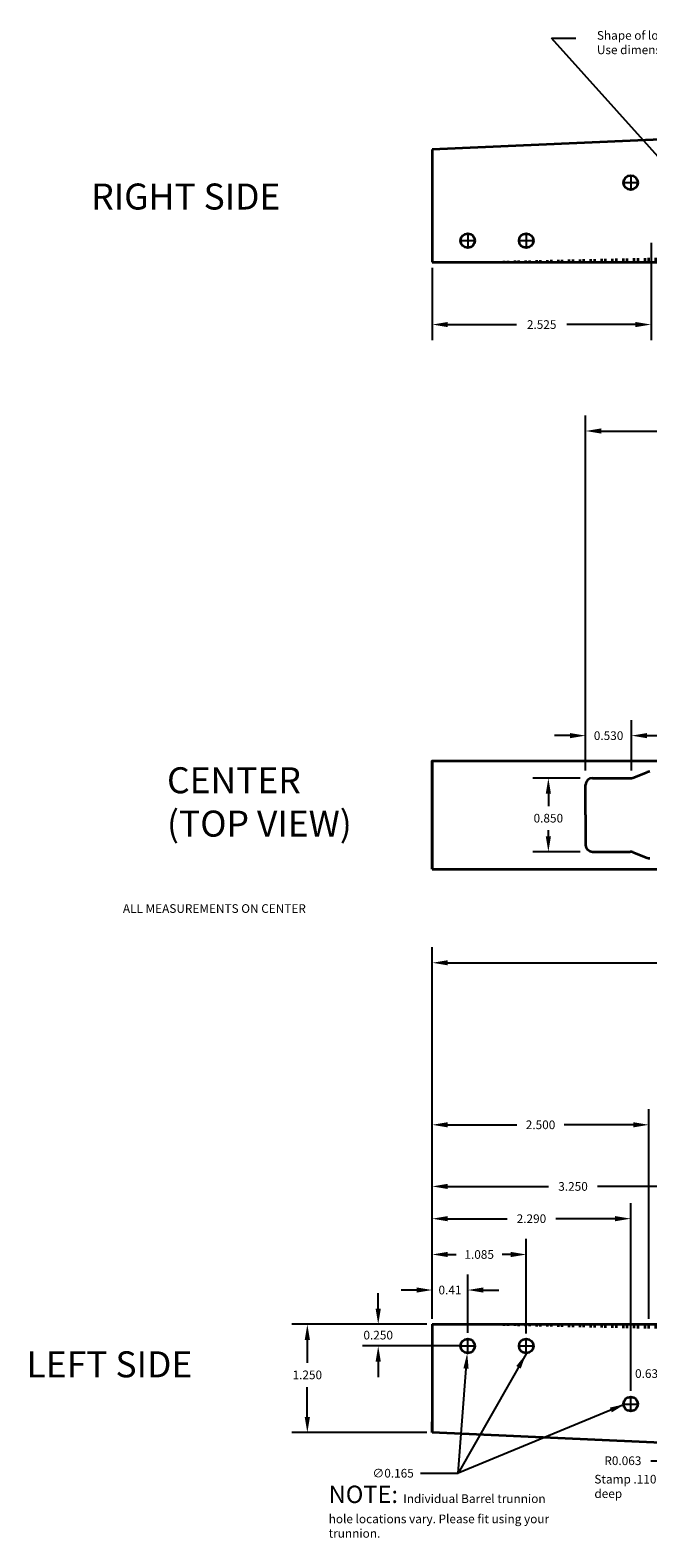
# Model space of a CAD drawing. Units: inches. Extents: x -3.6 to 16.1, y -0.6 to 17.2.
# Drawn here: x -3.6 to 3.5, y -0.2 to 17.2 of the extents above; entities that cross this region are included whole.
import ezdxf

# ---------------------------------------------------------------- set-up
doc = ezdxf.new("R2010")
doc.units = ezdxf.units.IN
doc.header["$MEASUREMENT"] = 0
doc.linetypes.add('ACAD_ISO03W100', pattern=[30, 12, -18])
doc.layers.add('dimensions', color=7, linetype='Continuous')
doc.layers.add('lines', color=1, linetype='Continuous', lineweight=35)
doc.dimstyles.get("Standard").update_dxf_attribs({"dimtxt": 0.18, "dimasz": 0.18, "dimexe": 0.18, "dimexo": 0.0625, "dimgap": 0.09, "dimtad": 0, "dimtih": 1, "dimtoh": 1, "dimdec": 3, "dimzin": 0, "dimdsep": 46, "dimtxsty": 'Standard', "dimcen": 0.09, "dimadec": 0, "dimazin": 0, "dimtfac": 1, "dimtdec": 3, "dimtofl": 0, "dimtmove": 0, "dimatfit": 3, "dimfxl": 0, "dimtolj": 1, "dimtzin": 0, "dimarcsym": 0})
pattern_1 = [(90, (0, 0), (-0.125, 3e-17), []), (90, (-0.0442, 0.0442), (-0.125, 3e-17), [])]

# ---------------------------------------------------------------- blocks, each defined once
blk = doc.blocks.new('*D7')
at = {"layer": 'Defpoints', "color": 0}
for p in [(2.77, 12.554), (2.77, 8.75), (11.25, 8.75)]:
    blk.add_point(p, dxfattribs=at)
at = {"layer": 'dimensions', "color": 0, "lineweight": -2}
for p, q in [((2.77, 8.812), (2.77, 12.734)), ((11.25, 8.812), (11.25, 12.734)), ((2.95, 12.554), (6.728, 12.554)), ((11.07, 12.554), (7.292, 12.554))]:
    blk.add_line(p, q, dxfattribs=at)
at = {"layer": 'dimensions', "color": 0}
for points in [[(2.95, 12.584), (2.95, 12.524), (2.77, 12.554)], [(11.07, 12.584), (11.07, 12.524), (11.25, 12.554)]]:
    blk.add_solid(points, dxfattribs=at)
at = {"layer": 'dimensions', "color": 0, "insert": (7.01, 12.554), "char_height": 0.1, "attachment_point": 5}
blk.add_mtext('\\A1;8.480', dxfattribs=at)
blk = doc.blocks.new('*D10')
at = {"layer": 'Defpoints', "color": 0}
for p in [(2.77, 8.55), (2.34, 7.7), (2.77, 7.7)]:
    blk.add_point(p, dxfattribs=at)
at = {"layer": 'dimensions', "color": 0, "lineweight": -2}
for p, q in [((2.708, 8.55), (2.16, 8.55)), ((2.34, 8.37), (2.34, 8.228)), ((2.34, 7.88), (2.34, 7.948)), ((2.708, 7.7), (2.16, 7.7))]:
    blk.add_line(p, q, dxfattribs=at)
at = {"layer": 'dimensions', "color": 0}
for points in [[(2.31, 8.37), (2.37, 8.37), (2.34, 8.55)], [(2.31, 7.88), (2.37, 7.88), (2.34, 7.7)]]:
    blk.add_solid(points, dxfattribs=at)
at = {"layer": 'dimensions', "color": 0, "insert": (2.34, 8.088), "char_height": 0.1, "attachment_point": 5}
blk.add_mtext('\\A1;0.850', dxfattribs=at)
blk = doc.blocks.new('*D11')
at = {"layer": 'Defpoints', "color": 0}
for p in [(1, 2.25), (-0.441, 1), (1, 1)]:
    blk.add_point(p, dxfattribs=at)
at = {"layer": 'dimensions', "color": 0, "lineweight": -2}
for p, q in [((0.938, 2.25), (-0.621, 2.25)), ((-0.441, 2.07), (-0.441, 1.806)), ((-0.441, 1.18), (-0.441, 1.526)), ((0.938, 1), (-0.621, 1))]:
    blk.add_line(p, q, dxfattribs=at)
at = {"layer": 'dimensions', "color": 0}
for points in [[(-0.471, 2.07), (-0.411, 2.07), (-0.441, 2.25)], [(-0.471, 1.18), (-0.411, 1.18), (-0.441, 1)]]:
    blk.add_solid(points, dxfattribs=at)
at = {"layer": 'dimensions', "color": 0, "insert": (-0.441, 1.666), "char_height": 0.1, "attachment_point": 5}
blk.add_mtext('\\A1;1.250', dxfattribs=at)
blk = doc.blocks.new('*D12')
at = {"layer": 'Defpoints', "color": 0}
for p in [(0.377, 2.25), (1, 2.25), (1.41, 2)]:
    blk.add_point(p, dxfattribs=at)
at = {"layer": 'dimensions', "color": 0, "lineweight": -2}
for p, q in [((0.377, 2.43), (0.377, 2.61)), ((0.938, 2.25), (0.197, 2.25)), ((1.347, 2), (0.197, 2)), ((0.377, 1.82), (0.377, 1.64))]:
    blk.add_line(p, q, dxfattribs=at)
at = {"layer": 'dimensions', "color": 0}
for points in [[(0.347, 2.43), (0.407, 2.43), (0.377, 2.25)], [(0.347, 1.82), (0.407, 1.82), (0.377, 2)]]:
    blk.add_solid(points, dxfattribs=at)
at = {"layer": 'dimensions', "color": 0, "insert": (0.377, 2.125), "char_height": 0.1, "attachment_point": 5}
blk.add_mtext('\\A1;0.250', dxfattribs=at)
blk = doc.blocks.new('*D13')
at = {"layer": 'Defpoints', "color": 0}
for p in [(1.404, 1.918), (1.416, 2.082)]:
    blk.add_point(p, dxfattribs=at)
at = {"layer": 'dimensions', "color": 0, "lineweight": -2}
for p, q in [((1.41, 1.91), (1.41, 2.09)), ((1.32, 2), (1.5, 2)), ((1.299, 0.532), (1.39, 1.738)), ((0.864, 0.532), (1.299, 0.532))]:
    blk.add_line(p, q, dxfattribs=at)
at = {"layer": 'dimensions', "color": 0}
blk.add_solid([(1.36, 1.741), (1.42, 1.736), (1.404, 1.918)], dxfattribs=at)
at = {"layer": 'dimensions', "color": 0, "insert": (0.549, 0.532), "char_height": 0.1, "attachment_point": 5}
blk.add_mtext('\\A1;∅0.165', dxfattribs=at)
blk = doc.blocks.new('*D14')
at = {"layer": 'Defpoints', "color": 0}
for p in [(3.29, 3.468), (1, 2.25), (3.29, 1.42)]:
    blk.add_point(p, dxfattribs=at)
at = {"layer": 'dimensions', "color": 0, "lineweight": -2}
for p, q in [((1, 2.312), (1, 3.648)), ((3.29, 1.482), (3.29, 3.648)), ((1.18, 3.468), (1.863, 3.468)), ((3.11, 3.468), (2.427, 3.468))]:
    blk.add_line(p, q, dxfattribs=at)
at = {"layer": 'dimensions', "color": 0}
for points in [[(1.18, 3.498), (1.18, 3.438), (1, 3.468)], [(3.11, 3.498), (3.11, 3.438), (3.29, 3.468)]]:
    blk.add_solid(points, dxfattribs=at)
at = {"layer": 'dimensions', "color": 0, "insert": (2.145, 3.468), "char_height": 0.1, "attachment_point": 5}
blk.add_mtext('\\A1;2.290', dxfattribs=at)
blk = doc.blocks.new('*D15')
at = {"layer": 'Defpoints', "color": 0}
for p in [(2.085, 3.055), (1, 2.25), (2.085, 2.083)]:
    blk.add_point(p, dxfattribs=at)
at = {"layer": 'dimensions', "color": 0, "lineweight": -2}
for p, q in [((1, 2.312), (1, 3.235)), ((2.085, 2.145), (2.085, 3.235)), ((1.18, 3.055), (1.277, 3.055)), ((1.905, 3.055), (1.808, 3.055))]:
    blk.add_line(p, q, dxfattribs=at)
at = {"layer": 'dimensions', "color": 0}
for points in [[(1.18, 3.085), (1.18, 3.025), (1, 3.055)], [(1.905, 3.085), (1.905, 3.025), (2.085, 3.055)]]:
    blk.add_solid(points, dxfattribs=at)
at = {"layer": 'dimensions', "color": 0, "insert": (1.542, 3.055), "char_height": 0.1, "attachment_point": 5}
blk.add_mtext('\\A1;1.085', dxfattribs=at)
blk = doc.blocks.new('*D16')
at = {"layer": 'Defpoints', "color": 0}
for p in [(1.41, 2.645), (1, 2.25), (1.41, 2.09)]:
    blk.add_point(p, dxfattribs=at)
at = {"layer": 'dimensions', "color": 0, "lineweight": -2}
for p, q in [((1, 2.313), (1, 2.825)), ((1.41, 2.153), (1.41, 2.825)), ((0.82, 2.645), (0.64, 2.645)), ((1.59, 2.645), (1.77, 2.645))]:
    blk.add_line(p, q, dxfattribs=at)
at = {"layer": 'dimensions', "color": 0}
for points in [[(0.82, 2.675), (0.82, 2.615), (1, 2.645)], [(1.59, 2.675), (1.59, 2.615), (1.41, 2.645)]]:
    blk.add_solid(points, dxfattribs=at)
at = {"layer": 'dimensions', "color": 0, "insert": (1.205, 2.645), "char_height": 0.1, "attachment_point": 5}
blk.add_mtext('\\A1;0.41', dxfattribs=at)
blk = doc.blocks.new('*D17')
at = {"layer": 'Defpoints', "color": 0}
for p in [(3.3, 9.04), (2.77, 8.575), (3.3, 8.575)]:
    blk.add_point(p, dxfattribs=at)
at = {"layer": 'dimensions', "color": 0, "lineweight": -2}
for p, q in [((2.77, 8.638), (2.77, 9.22)), ((3.3, 8.638), (3.3, 9.22)), ((2.59, 9.04), (2.41, 9.04)), ((3.48, 9.04), (3.66, 9.04))]:
    blk.add_line(p, q, dxfattribs=at)
at = {"layer": 'dimensions', "color": 0}
for points in [[(2.59, 9.07), (2.59, 9.01), (2.77, 9.04)], [(3.48, 9.07), (3.48, 9.01), (3.3, 9.04)]]:
    blk.add_solid(points, dxfattribs=at)
at = {"layer": 'dimensions', "color": 0, "insert": (3.035, 9.04), "char_height": 0.1, "attachment_point": 5}
blk.add_mtext('\\A1;0.530', dxfattribs=at)
blk = doc.blocks.new('*D48')
at = {"layer": 'Defpoints', "color": 0}
for p in [(1, 4.551), (1, 2.25), (3.5, 2.25)]:
    blk.add_point(p, dxfattribs=at)
at = {"layer": 'dimensions', "color": 0, "lineweight": -2}
for p, q in [((1, 2.312), (1, 4.731)), ((3.5, 2.312), (3.5, 4.731)), ((1.18, 4.551), (1.977, 4.551)), ((3.32, 4.551), (2.523, 4.551))]:
    blk.add_line(p, q, dxfattribs=at)
at = {"layer": 'dimensions', "color": 0}
for points in [[(1.18, 4.581), (1.18, 4.521), (1, 4.551)], [(3.32, 4.581), (3.32, 4.521), (3.5, 4.551)]]:
    blk.add_solid(points, dxfattribs=at)
at = {"layer": 'dimensions', "color": 0, "insert": (2.25, 4.551), "char_height": 0.1, "attachment_point": 5}
blk.add_mtext('\\A1;2.500', dxfattribs=at)
blk = doc.blocks.new('*D56')
at = {"layer": 'Defpoints', "color": 0}
for p in [(4.568, 1.681), (3.933, 1.332), (4.568, 1.332)]:
    blk.add_point(p, dxfattribs=at)
at = {"layer": 'dimensions', "color": 0, "lineweight": -2}
for p, q in [((3.933, 1.395), (3.933, 1.831)), ((4.568, 1.395), (4.568, 1.831)), ((3.933, 1.681), (3.752, 1.681)), ((4.388, 1.681), (4.112, 1.681))]:
    blk.add_line(p, q, dxfattribs=at)
at = {"layer": 'dimensions', "color": 0}
for points in [[(4.112, 1.711), (4.112, 1.651), (3.933, 1.681)], [(4.388, 1.711), (4.388, 1.651), (4.568, 1.681)]]:
    blk.add_solid(points, dxfattribs=at)
at = {"layer": 'dimensions', "color": 0, "insert": (3.511, 1.681), "char_height": 0.1, "attachment_point": 5}
blk.add_mtext('\\A1;0.635', dxfattribs=at)
blk = doc.blocks.new('*D57')
at = {"layer": 'Defpoints', "color": 0}
for p in [(1, 3.84), (1, 2.25), (4.25, 1.482)]:
    blk.add_point(p, dxfattribs=at)
at = {"layer": 'dimensions', "color": 0, "lineweight": -2}
for p, q in [((1, 2.312), (1, 4.02)), ((4.25, 1.545), (4.25, 4.02)), ((1.18, 3.84), (2.343, 3.84)), ((4.07, 3.84), (2.907, 3.84))]:
    blk.add_line(p, q, dxfattribs=at)
at = {"layer": 'dimensions', "color": 0}
for points in [[(1.18, 3.87), (1.18, 3.81), (1, 3.84)], [(4.07, 3.87), (4.07, 3.81), (4.25, 3.84)]]:
    blk.add_solid(points, dxfattribs=at)
at = {"layer": 'dimensions', "color": 0, "insert": (2.625, 3.84), "char_height": 0.1, "attachment_point": 5}
blk.add_mtext('\\A1;3.250', dxfattribs=at)
blk = doc.blocks.new('*D58')
at = {"layer": 'Defpoints', "color": 0}
for p in [(3.973, 1.274), (3.995, 1.332)]:
    blk.add_point(p, dxfattribs=at)
at = {"layer": 'dimensions', "color": 0, "lineweight": -2}
for p, q in [((3.995, 1.242), (3.995, 1.422)), ((3.905, 1.332), (4.085, 1.332)), ((3.753, 0.676), (3.911, 1.105)), ((3.523, 0.676), (3.753, 0.676))]:
    blk.add_line(p, q, dxfattribs=at)
at = {"layer": 'dimensions', "color": 0}
blk.add_solid([(3.883, 1.115), (3.939, 1.094), (3.973, 1.274)], dxfattribs=at)
at = {"layer": 'dimensions', "color": 0, "insert": (3.2, 0.676), "char_height": 0.1, "attachment_point": 5}
blk.add_mtext('\\A1;R0.063', dxfattribs=at)
blk = doc.blocks.new('*D70')
at = {"layer": 'Defpoints', "color": 0, "linetype": 'ACAD_ISO03W100'}
for p in [(11.25, 6.42), (1, 2.25), (11.25, 2.05)]:
    blk.add_point(p, dxfattribs=at)
at = {"layer": 'dimensions', "color": 0, "linetype": 'ACAD_ISO03W100', "lineweight": -2}
for p, q in [((1, 2.312), (1, 6.6)), ((11.25, 2.112), (11.25, 6.6)), ((1.18, 6.42), (5.818, 6.42)), ((11.07, 6.42), (6.432, 6.42))]:
    blk.add_line(p, q, dxfattribs=at)
at = {"layer": 'dimensions', "color": 0, "linetype": 'ACAD_ISO03W100'}
for points in [[(1.18, 6.45), (1.18, 6.39), (1, 6.42)], [(11.07, 6.45), (11.07, 6.39), (11.25, 6.42)]]:
    blk.add_solid(points, dxfattribs=at)
at = {"layer": 'dimensions', "color": 0, "linetype": 'ACAD_ISO03W100', "insert": (6.125, 6.42), "char_height": 0.1, "attachment_point": 5}
blk.add_mtext('\\A1;10.250', dxfattribs=at)
blk = doc.blocks.new('*D72')
at = {"layer": 'Defpoints', "color": 0, "linetype": 'ByBlock'}
for p in [(3.525, 14.785), (1, 14.5), (3.525, 13.782)]:
    blk.add_point(p, dxfattribs=at)
at = {"layer": 'dimensions', "color": 0, "linetype": 'ByBlock', "lineweight": -2}
for p, q in [((3.525, 14.723), (3.525, 13.602)), ((1, 14.438), (1, 13.602)), ((1.18, 13.782), (1.973, 13.782)), ((3.345, 13.782), (2.553, 13.782))]:
    blk.add_line(p, q, dxfattribs=at)
at = {"layer": 'dimensions', "color": 0, "linetype": 'ByBlock'}
for points in [[(1.18, 13.812), (1.18, 13.752), (1, 13.782)], [(3.345, 13.812), (3.345, 13.752), (3.525, 13.782)]]:
    blk.add_solid(points, dxfattribs=at)
at = {"layer": 'dimensions', "color": 0, "linetype": 'ByBlock', "insert": (2.263, 13.782), "char_height": 0.1, "attachment_point": 5}
blk.add_mtext('\\A1;2.525', dxfattribs=at)

msp = doc.modelspace()

# ---------------------------------------------------------------- hatches: boundary and pattern name
at = {"layer": 'lines'}
h = msp.add_hatch(dxfattribs=at)
h.set_pattern_fill('STEEL', color=256, angle=45, style=0)
h.set_pattern_definition(pattern_1)
edge = h.paths.add_edge_path()
edge.add_line((3.5, 14.55), (9.5, 14.55))
edge.add_line((10.95, 14.5), (1, 14.5))
h = msp.add_hatch(dxfattribs=at)
h.set_pattern_fill('STEEL', color=256, angle=45, style=0)
h.set_pattern_definition(pattern_1)
edge = h.paths.add_edge_path()
edge.add_line((3.5, 2.2), (9.5, 2.2))
edge.add_line((10.95, 2.25), (1, 2.25))

# ---------------------------------------------------------------- linework, layer by layer
at = {"layer": 'dimensions'}
for p, q in [((3.29, 15.51), (3.29, 15.33)), ((3.2, 15.42), (3.38, 15.42)), ((1.41, 14.84), (1.41, 14.66)), ((2.085, 14.84), (2.085, 14.66)), ((1.32, 14.75), (1.5, 14.75)), ((1.995, 14.75), (2.175, 14.75)), ((1.41, 1.91), (1.41, 2.09)), ((2.085, 1.91), (2.085, 2.09)), ((1.32, 2), (1.5, 2)), ((1.995, 2), (2.175, 2)), ((3.29, 1.24), (3.29, 1.42)), ((3.2, 1.33), (3.38, 1.33))]:
    msp.add_line(p, q, dxfattribs=at)
at = {"layer": 'lines', "color": 1}
for p, q in [((11.25, 16.25), (1, 15.8)), ((1, 15.8), (1, 14.5)), ((1, 8.75), (11.25, 8.75)), ((2.8481, 8.55), (3.2855, 8.55)), ((3.3135, 8.5552), (3.4815, 8.6198)), ((2.77, 8.125), (2.77, 8.4719)), ((2.77, 8.125), (2.77, 7.7781)), ((2.8481, 7.7), (3.2855, 7.7)), ((3.3135, 7.6948), (3.4815, 7.6302)), ((1, 7.5), (11.25, 7.5)), ((1, 2.25), (1, 1)), ((1, 1), (1, 1.125)), ((11.25, 0.55), (1, 1))]:
    msp.add_line(p, q, dxfattribs=at)
at = {"layer": 'lines', "linetype": 'ByBlock'}
for p, q in [((1, 14.5), (10.95, 14.5)), ((1, 2.25), (10.95, 2.25))]:
    msp.add_line(p, q, dxfattribs=at)
at = {"layer": 'lines', "color": 1}
msp.add_lwpolyline([(1, 7.5), (1, 7.5), (1, 8.75), (1, 8.75)], close=True, dxfattribs=at)
for centre in [(3.29, 15.42), (1.41, 14.75), (2.085, 14.75), (1.41, 2), (2.085, 2), (3.29, 1.33)]:
    msp.add_circle(centre, 0.0825, dxfattribs=at)
for centre, start, end in [((2.8481, 8.4719), 90, 180), ((3.2855, 8.6281), 270, 291.03751), ((3.5095, 8.5469), 90, 111.03751), ((2.8481, 7.7781), 180, 270), ((3.2855, 7.6219), 68.96249, 90), ((3.5095, 7.7031), 248.96249, 270)]:
    msp.add_arc(centre, 0.0781, start, end, dxfattribs=at)

# ---------------------------------------------------------------- texts
at = {"layer": 'dimensions'}
msp.add_text('LEFT SIDE', height=0.3, dxfattribs=at).set_placement((-3.6806, 1.638))
at = {"layer": 'dimensions', "linetype": 'ByBlock', "insert": (2.9004, 17.1677), "char_height": 0.1, "width": 2.3136, "attachment_point": 1}
msp.add_mtext('Shape of lower rail is not accurate. Use dimensions for location only.', dxfattribs=at)
at = {"layer": 'dimensions', "attachment_point": 1}
for s, insert, char_height, width in [('RIGHT SIDE', (-2.9345, 15.4087), 0.3, 3.5318), ('CENTER (TOP VIEW)', (-2.06, 8.6752), 0.3, 2.544428), ('ALL MEASUREMENTS ON CENTER', (-2.5689, 7.0956), 0.1, 2.836), ('NOTE: {\\H0.5x;Individual Barrel trunnion hole locations vary. Please fit using your  trunnion.}', (-0.1944, 0.3883), 0.2, 2.666396), ('Stamp .110 deep', (2.8714, 0.5132), 0.1, 0.998118)]:
    msp.add_mtext(s, dxfattribs=dict(at, insert=insert, char_height=char_height, width=width))

# ---------------------------------------------------------------- dimensions: what is measured, and where the dimension line sits
at = {"layer": 'dimensions', "linetype": 'ByBlock'}
dim = msp.add_linear_dim(base=(3.525, 13.7824), p1=(1, 14.5), p2=(3.525, 14.785), dimstyle='Standard', override={"dimtxt": 0.1}, dxfattribs=at)
dim.commit()
dim.dimension.update_dxf_attribs({"geometry": '*D72', "text_midpoint": (2.2625, 13.7824)})
at = {"layer": 'dimensions'}
for base, p1, p2, override, picture, middle in [((2.77, 12.5543), (11.25, 8.75), (2.77, 8.75), {"dimtxt": 0.1}, '*D7', (7.01, 12.5543)), ((3.3, 9.0399), (2.77, 8.575), (3.3, 8.575), {"dimtxt": 0.1}, '*D17', (3.035, 9.0399)), ((1, 4.551), (3.5, 2.25), (1, 2.25), {"dimtxt": 0.1}, '*D48', (2.25, 4.551)), ((1, 3.84), (4.25, 1.4823), (1, 2.25), {"dimtxt": 0.1}, '*D57', (2.625, 3.84)), ((3.29, 3.4681), (1, 2.25), (3.29, 1.42), {"dimtxt": 0.1}, '*D14', (2.145, 3.4681)), ((2.085, 3.0553), (1, 2.25), (2.085, 2.0825), {"dimtxt": 0.1}, '*D15', (1.5425, 3.0553)), ((4.5675, 1.6814), (3.9325, 1.3323), (4.5675, 1.3323), {"dimtxt": 0.1, "dimexe": 0.15, "dimgap": 0.05}, '*D56', (3.5108, 1.6814))]:
    dim = msp.add_linear_dim(base=base, p1=p1, p2=p2, dimstyle='Standard', override=override, dxfattribs=at)
    dim.commit()
    dim.dimension.update_dxf_attribs({"geometry": picture, "text_midpoint": middle, "dimtype": 160})
for base, p1, p2, picture, middle in [((2.3401, 7.7), (2.77, 8.55), (2.77, 7.7), '*D10', (2.3401, 8.088)), ((0.3773, 2.25), (1.41, 2), (1, 2.25), '*D12', (0.3773, 2.125)), ((-0.4409, 1), (1, 2.25), (1, 1), '*D11', (-0.4409, 1.6657))]:
    dim = msp.add_linear_dim(base=base, p1=p1, p2=p2, angle=90, dimstyle='Standard', override={"dimtxt": 0.1}, dxfattribs=at)
    dim.commit()
    dim.dimension.update_dxf_attribs({"geometry": picture, "text_midpoint": middle, "dimtype": 160})
at = {"layer": 'dimensions', "linetype": 'ACAD_ISO03W100'}
dim = msp.add_linear_dim(base=(11.25, 6.4198), p1=(1, 2.25), p2=(11.25, 2.05), dimstyle='Standard', override={"dimtxt": 0.1}, dxfattribs=at)
dim.commit()
dim.dimension.update_dxf_attribs({"geometry": '*D70', "text_midpoint": (6.125, 6.4198)})
at = {"layer": 'dimensions'}
dim = msp.add_linear_dim(base=(1.41, 2.6448), p1=(1, 2.25), p2=(1.41, 2.09), text='0.41', dimstyle='Standard', override={"dimtxt": 0.1}, dxfattribs=at)
dim.commit()
dim.dimension.update_dxf_attribs({"geometry": '*D16', "text_midpoint": (1.205, 2.6448), "dimtype": 160})
dim = msp.add_diameter_dim_2p(p1=(1.4162, 2.0823), p2=(1.4038, 1.9177), dimstyle='Standard', override={"dimtxt": 0.1}, dxfattribs=at)
dim.commit()
dim.dimension.update_dxf_attribs({"geometry": '*D13', "text_midpoint": (0.5486, 0.5323), "dimtype": 163})
dim = msp.add_radius_dim(center=(3.995, 1.3323), mpoint=(3.9734, 1.2737), dimstyle='Standard', override={"dimtxt": 0.1}, dxfattribs=at)
dim.commit()
dim.dimension.update_dxf_attribs({"geometry": '*D58', "text_midpoint": (3.1995, 0.6759), "dimtype": 164})

# ---------------------------------------------------------------- leaders
at = {"layer": 'dimensions', "linetype": 'ByBlock'}
msp.add_leader([(4.0247, 15.25), (2.3772, 17.0863), (2.6562, 17.0863)], dimstyle='Standard', override={"dimgap": 0.09, "dimtad": 0}, dxfattribs=at)
at = {"layer": 'dimensions'}
for points in [[(2.085, 1.91), (1.2986, 0.5323)], [(3.2275, 1.33), (1.2986, 0.5323)]]:
    msp.add_leader(points, dimstyle='Standard', override={"dimgap": 0.09, "dimtad": 0}, dxfattribs=at)

doc.saveas('drawing.dxf')
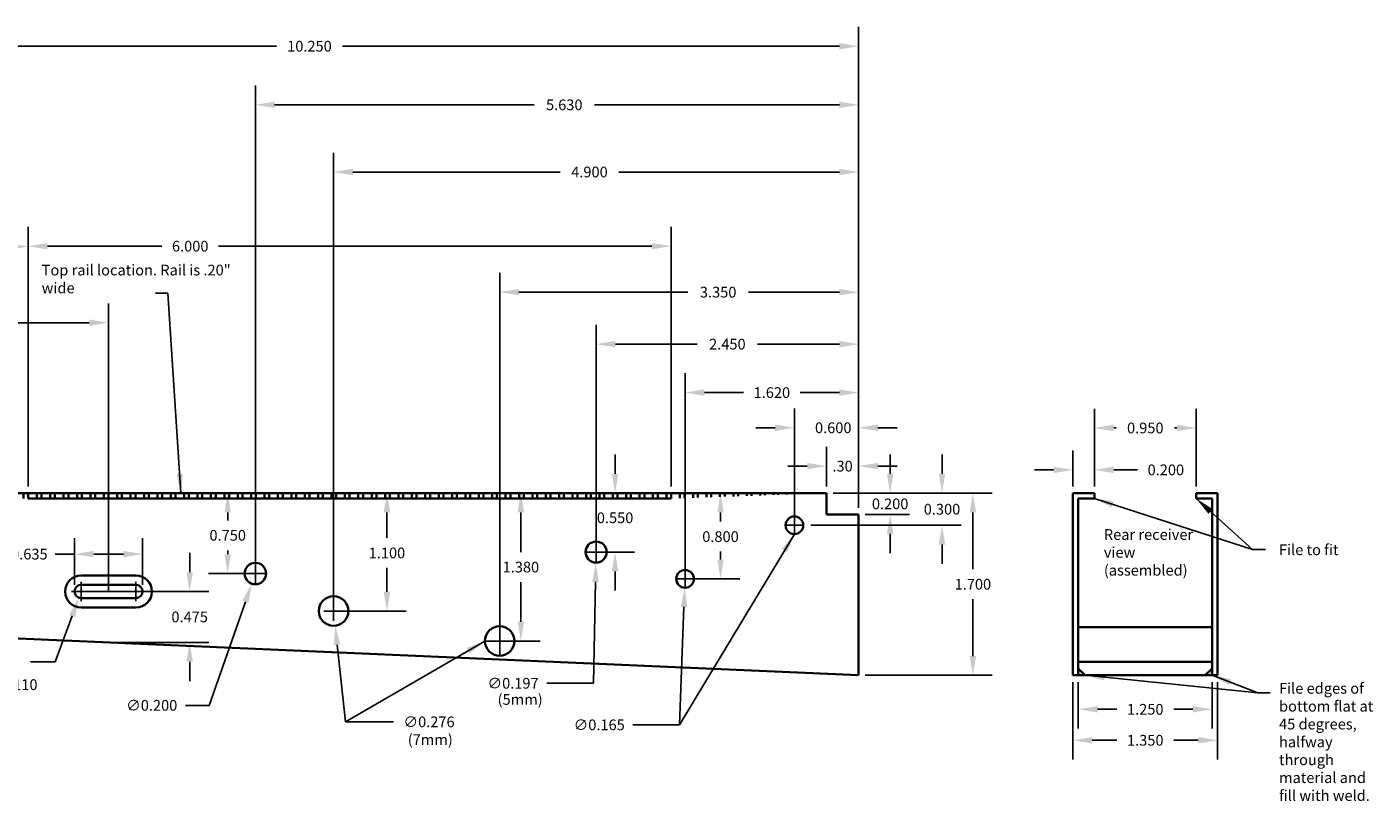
# Model space of a CAD drawing. Units: inches. Extents: x -3.6 to 16.1, y -0.6 to 17.2.
# Drawn here: x 3.5 to 16.1, y -0.6 to 6.6 of the extents above; entities that cross this region are included whole.
import ezdxf

# ---------------------------------------------------------------- set-up
doc = ezdxf.new("R2010")
doc.units = ezdxf.units.IN
doc.header["$MEASUREMENT"] = 0
doc.linetypes.add('ACAD_ISO03W100', pattern=[30, 12, -18])
doc.layers.add('dimensions', color=7, linetype='Continuous')
doc.layers.add('lines', color=1, linetype='Continuous', lineweight=35)
doc.dimstyles.get("Standard").update_dxf_attribs({"dimtxt": 0.18, "dimasz": 0.18, "dimexe": 0.18, "dimexo": 0.0625, "dimgap": 0.09, "dimtad": 0, "dimtih": 1, "dimtoh": 1, "dimdec": 3, "dimzin": 0, "dimdsep": 46, "dimtxsty": 'Standard', "dimcen": 0.09, "dimadec": 0, "dimazin": 0, "dimtfac": 1, "dimtdec": 3, "dimtofl": 0, "dimtmove": 0, "dimatfit": 3, "dimfxl": 0, "dimtolj": 1, "dimtzin": 0, "dimarcsym": 0})

# ---------------------------------------------------------------- blocks, each defined once
blk = doc.blocks.new('*D23')
at = {"layer": 'Defpoints', "color": 0}
for p in [(11.25, 5.873), (11.25, 2.25), (5.62, 1.5)]:
    blk.add_point(p, dxfattribs=at)
at = {"layer": 'dimensions', "color": 0, "lineweight": -2}
for p, q in [((5.62, 1.563), (5.62, 6.053)), ((11.25, 2.312), (11.25, 6.053)), ((5.8, 5.873), (8.221, 5.873)), ((11.07, 5.873), (8.785, 5.873))]:
    blk.add_line(p, q, dxfattribs=at)
at = {"layer": 'dimensions', "color": 0}
for points in [[(5.8, 5.903), (5.8, 5.843), (5.62, 5.873)], [(11.07, 5.903), (11.07, 5.843), (11.25, 5.873)]]:
    blk.add_solid(points, dxfattribs=at)
at = {"layer": 'dimensions', "color": 0, "insert": (8.503, 5.873), "char_height": 0.1, "attachment_point": 5}
blk.add_mtext('\\A1;5.630', dxfattribs=at)
blk = doc.blocks.new('*D24')
at = {"layer": 'Defpoints', "color": 0}
for p in [(6.35, 5.246), (11.25, 2.25), (6.35, 1.15)]:
    blk.add_point(p, dxfattribs=at)
at = {"layer": 'dimensions', "color": 0, "lineweight": -2}
for p, q in [((6.35, 1.213), (6.35, 5.426)), ((11.25, 2.312), (11.25, 5.426)), ((6.53, 5.246), (8.465, 5.246)), ((11.07, 5.246), (9.011, 5.246))]:
    blk.add_line(p, q, dxfattribs=at)
at = {"layer": 'dimensions', "color": 0}
for points in [[(6.53, 5.276), (6.53, 5.216), (6.35, 5.246)], [(11.07, 5.276), (11.07, 5.216), (11.25, 5.246)]]:
    blk.add_solid(points, dxfattribs=at)
at = {"layer": 'dimensions', "color": 0, "insert": (8.738, 5.246), "char_height": 0.1, "attachment_point": 5}
blk.add_mtext('\\A1;4.900', dxfattribs=at)
blk = doc.blocks.new('*D25')
at = {"layer": 'Defpoints', "color": 0}
for p in [(7.9, 4.125), (11.25, 2.25), (7.9, 0.87)]:
    blk.add_point(p, dxfattribs=at)
at = {"layer": 'dimensions', "color": 0, "lineweight": -2}
for p, q in [((7.9, 0.933), (7.9, 4.305)), ((11.25, 2.312), (11.25, 4.305)), ((8.08, 4.125), (9.657, 4.125)), ((11.07, 4.125), (10.221, 4.125))]:
    blk.add_line(p, q, dxfattribs=at)
at = {"layer": 'dimensions', "color": 0}
for points in [[(8.08, 4.155), (8.08, 4.095), (7.9, 4.125)], [(11.07, 4.155), (11.07, 4.095), (11.25, 4.125)]]:
    blk.add_solid(points, dxfattribs=at)
at = {"layer": 'dimensions', "color": 0, "insert": (9.939, 4.125), "char_height": 0.1, "attachment_point": 5}
blk.add_mtext('\\A1;3.350', dxfattribs=at)
blk = doc.blocks.new('*D26')
at = {"layer": 'Defpoints', "color": 0}
for p in [(8.8, 3.64), (11.25, 2.25), (8.8, 1.7)]:
    blk.add_point(p, dxfattribs=at)
at = {"layer": 'dimensions', "color": 0, "lineweight": -2}
for p, q in [((8.8, 1.762), (8.8, 3.82)), ((11.25, 2.312), (11.25, 3.82)), ((8.98, 3.64), (9.743, 3.64)), ((11.07, 3.64), (10.307, 3.64))]:
    blk.add_line(p, q, dxfattribs=at)
at = {"layer": 'dimensions', "color": 0}
for points in [[(8.98, 3.67), (8.98, 3.61), (8.8, 3.64)], [(11.07, 3.67), (11.07, 3.61), (11.25, 3.64)]]:
    blk.add_solid(points, dxfattribs=at)
at = {"layer": 'dimensions', "color": 0, "insert": (10.025, 3.64), "char_height": 0.1, "attachment_point": 5}
blk.add_mtext('\\A1;2.450', dxfattribs=at)
blk = doc.blocks.new('*D27')
at = {"layer": 'Defpoints', "color": 0}
for p in [(9.63, 3.188), (11.25, 2.25), (9.63, 1.45)]:
    blk.add_point(p, dxfattribs=at)
at = {"layer": 'dimensions', "color": 0, "lineweight": -2}
for p, q in [((9.63, 1.512), (9.63, 3.368)), ((11.25, 2.312), (11.25, 3.368)), ((9.81, 3.188), (10.175, 3.188)), ((11.07, 3.188), (10.705, 3.188))]:
    blk.add_line(p, q, dxfattribs=at)
at = {"layer": 'dimensions', "color": 0}
for points in [[(9.81, 3.218), (9.81, 3.158), (9.63, 3.188)], [(11.07, 3.218), (11.07, 3.158), (11.25, 3.188)]]:
    blk.add_solid(points, dxfattribs=at)
at = {"layer": 'dimensions', "color": 0, "insert": (10.44, 3.188), "char_height": 0.1, "attachment_point": 5}
blk.add_mtext('\\A1;1.620', dxfattribs=at)
blk = doc.blocks.new('*D28')
at = {"layer": 'Defpoints', "color": 0}
for p in [(9.63, 2.25), (9.961, 2.25), (9.63, 1.45)]:
    blk.add_point(p, dxfattribs=at)
at = {"layer": 'dimensions', "color": 0, "lineweight": -2}
for p, q in [((9.693, 2.25), (10.141, 2.25)), ((9.961, 2.07), (9.961, 1.984)), ((9.961, 1.63), (9.961, 1.704)), ((9.693, 1.45), (10.141, 1.45))]:
    blk.add_line(p, q, dxfattribs=at)
at = {"layer": 'dimensions', "color": 0}
for points in [[(9.931, 2.07), (9.991, 2.07), (9.961, 2.25)], [(9.931, 1.63), (9.991, 1.63), (9.961, 1.45)]]:
    blk.add_solid(points, dxfattribs=at)
at = {"layer": 'dimensions', "color": 0, "insert": (9.961, 1.844), "char_height": 0.1, "attachment_point": 5}
blk.add_mtext('\\A1;0.800', dxfattribs=at)
blk = doc.blocks.new('*D29')
at = {"layer": 'Defpoints', "color": 0}
for p in [(8.8, 2.25), (8.977, 2.25), (8.8, 1.7)]:
    blk.add_point(p, dxfattribs=at)
at = {"layer": 'dimensions', "color": 0, "lineweight": -2}
for p, q in [((8.977, 2.43), (8.977, 2.61)), ((8.863, 2.25), (9.157, 2.25)), ((8.863, 1.7), (9.157, 1.7)), ((8.977, 1.52), (8.977, 1.34))]:
    blk.add_line(p, q, dxfattribs=at)
at = {"layer": 'dimensions', "color": 0}
for points in [[(8.947, 2.43), (9.007, 2.43), (8.977, 2.25)], [(8.947, 1.52), (9.007, 1.52), (8.977, 1.7)]]:
    blk.add_solid(points, dxfattribs=at)
at = {"layer": 'dimensions', "color": 0, "insert": (8.977, 2.02), "char_height": 0.1, "attachment_point": 5}
blk.add_mtext('\\A1;0.550', dxfattribs=at)
blk = doc.blocks.new('*D30')
at = {"layer": 'Defpoints', "color": 0}
for p in [(5.362, 2.25), (5.62, 2.25), (5.62, 1.5)]:
    blk.add_point(p, dxfattribs=at)
at = {"layer": 'dimensions', "color": 0, "lineweight": -2}
for p, q in [((5.558, 2.25), (5.182, 2.25)), ((5.362, 2.07), (5.362, 1.996)), ((5.362, 1.68), (5.362, 1.716)), ((5.558, 1.5), (5.182, 1.5))]:
    blk.add_line(p, q, dxfattribs=at)
at = {"layer": 'dimensions', "color": 0}
for points in [[(5.332, 2.07), (5.392, 2.07), (5.362, 2.25)], [(5.332, 1.68), (5.392, 1.68), (5.362, 1.5)]]:
    blk.add_solid(points, dxfattribs=at)
at = {"layer": 'dimensions', "color": 0, "insert": (5.362, 1.856), "char_height": 0.1, "attachment_point": 5}
blk.add_mtext('\\A1;0.750', dxfattribs=at)
blk = doc.blocks.new('*D31')
at = {"layer": 'Defpoints', "color": 0}
for p in [(6.35, 2.25), (6.848, 2.25), (6.35, 1.15)]:
    blk.add_point(p, dxfattribs=at)
at = {"layer": 'dimensions', "color": 0, "lineweight": -2}
for p, q in [((6.413, 2.25), (7.028, 2.25)), ((6.848, 2.07), (6.848, 1.832)), ((6.848, 1.33), (6.848, 1.552)), ((6.413, 1.15), (7.028, 1.15))]:
    blk.add_line(p, q, dxfattribs=at)
at = {"layer": 'dimensions', "color": 0}
for points in [[(6.818, 2.07), (6.878, 2.07), (6.848, 2.25)], [(6.818, 1.33), (6.878, 1.33), (6.848, 1.15)]]:
    blk.add_solid(points, dxfattribs=at)
at = {"layer": 'dimensions', "color": 0, "insert": (6.848, 1.692), "char_height": 0.1, "attachment_point": 5}
blk.add_mtext('\\A1;1.100', dxfattribs=at)
blk = doc.blocks.new('*D32')
at = {"layer": 'Defpoints', "color": 0}
for p in [(7.9, 2.25), (8.098, 2.25), (7.9, 0.87)]:
    blk.add_point(p, dxfattribs=at)
at = {"layer": 'dimensions', "color": 0, "lineweight": -2}
for p, q in [((7.963, 2.25), (8.278, 2.25)), ((8.098, 2.07), (8.098, 1.7)), ((8.098, 1.05), (8.098, 1.42)), ((7.963, 0.87), (8.278, 0.87))]:
    blk.add_line(p, q, dxfattribs=at)
at = {"layer": 'dimensions', "color": 0}
for points in [[(8.068, 2.07), (8.128, 2.07), (8.098, 2.25)], [(8.068, 1.05), (8.128, 1.05), (8.098, 0.87)]]:
    blk.add_solid(points, dxfattribs=at)
at = {"layer": 'dimensions', "color": 0, "insert": (8.098, 1.56), "char_height": 0.1, "attachment_point": 5}
blk.add_mtext('\\A1;1.380', dxfattribs=at)
blk = doc.blocks.new('*D33')
at = {"layer": 'Defpoints', "color": 0}
for p in [(10.65, 2.86), (11.25, 2.25), (10.65, 1.95)]:
    blk.add_point(p, dxfattribs=at)
at = {"layer": 'dimensions', "color": 0, "lineweight": -2}
for p, q in [((10.65, 2.013), (10.65, 3.04)), ((11.25, 2.313), (11.25, 3.04)), ((10.47, 2.86), (10.29, 2.86)), ((11.43, 2.86), (11.61, 2.86))]:
    blk.add_line(p, q, dxfattribs=at)
at = {"layer": 'dimensions', "color": 0}
for points in [[(10.47, 2.89), (10.47, 2.83), (10.65, 2.86)], [(11.43, 2.89), (11.43, 2.83), (11.25, 2.86)]]:
    blk.add_solid(points, dxfattribs=at)
at = {"layer": 'dimensions', "color": 0, "insert": (11.013, 2.86), "char_height": 0.1, "attachment_point": 5}
blk.add_mtext('\\A1;0.600', dxfattribs=at)
blk = doc.blocks.new('*D34')
at = {"layer": 'Defpoints', "color": 0}
for p in [(11.25, 2.25), (11.25, 0.55), (12.316, 0.55)]:
    blk.add_point(p, dxfattribs=at)
at = {"layer": 'dimensions', "color": 0, "lineweight": -2}
for p, q in [((11.312, 2.25), (12.496, 2.25)), ((12.316, 2.07), (12.316, 1.54)), ((12.316, 0.73), (12.316, 1.26)), ((11.312, 0.55), (12.496, 0.55))]:
    blk.add_line(p, q, dxfattribs=at)
at = {"layer": 'dimensions', "color": 0}
for points in [[(12.286, 2.07), (12.346, 2.07), (12.316, 2.25)], [(12.286, 0.73), (12.346, 0.73), (12.316, 0.55)]]:
    blk.add_solid(points, dxfattribs=at)
at = {"layer": 'dimensions', "color": 0, "insert": (12.316, 1.4), "char_height": 0.1, "attachment_point": 5}
blk.add_mtext('\\A1;1.700', dxfattribs=at)
blk = doc.blocks.new('*D47')
at = {"layer": 'Defpoints', "color": 0}
for p in [(9.633, 1.532), (9.627, 1.368)]:
    blk.add_point(p, dxfattribs=at)
at = {"layer": 'dimensions', "color": 0, "lineweight": -2}
for p, q in [((9.63, 1.36), (9.63, 1.54)), ((9.54, 1.45), (9.72, 1.45)), ((9.579, 0.088), (9.62, 1.188)), ((9.144, 0.088), (9.579, 0.088))]:
    blk.add_line(p, q, dxfattribs=at)
at = {"layer": 'dimensions', "color": 0}
blk.add_solid([(9.59, 1.189), (9.65, 1.187), (9.627, 1.368)], dxfattribs=at)
at = {"layer": 'dimensions', "color": 0, "insert": (8.829, 0.088), "char_height": 0.1, "attachment_point": 5}
blk.add_mtext('\\A1;∅0.165', dxfattribs=at)
blk = doc.blocks.new('*D48')
at = {"layer": 'Defpoints', "color": 0}
for p in [(1, 4.551), (1, 2.25), (3.5, 2.25)]:
    blk.add_point(p, dxfattribs=at)
at = {"layer": 'dimensions', "color": 0, "lineweight": -2}
for p, q in [((1, 2.312), (1, 4.731)), ((3.5, 2.312), (3.5, 4.731)), ((1.18, 4.551), (1.977, 4.551)), ((3.32, 4.551), (2.523, 4.551))]:
    blk.add_line(p, q, dxfattribs=at)
at = {"layer": 'dimensions', "color": 0}
for points in [[(1.18, 4.581), (1.18, 4.521), (1, 4.551)], [(3.32, 4.581), (3.32, 4.521), (3.5, 4.551)]]:
    blk.add_solid(points, dxfattribs=at)
at = {"layer": 'dimensions', "color": 0, "insert": (2.25, 4.551), "char_height": 0.1, "attachment_point": 5}
blk.add_mtext('\\A1;2.500', dxfattribs=at)
blk = doc.blocks.new('*D49')
at = {"layer": 'Defpoints', "color": 0}
for p in [(3.5, 4.554), (3.5, 2.312), (9.5, 2.25)]:
    blk.add_point(p, dxfattribs=at)
at = {"layer": 'dimensions', "color": 0, "lineweight": -2}
for p, q in [((3.5, 2.375), (3.5, 4.734)), ((9.5, 2.312), (9.5, 4.734)), ((3.68, 4.554), (4.747, 4.554)), ((9.32, 4.554), (5.277, 4.554))]:
    blk.add_line(p, q, dxfattribs=at)
at = {"layer": 'dimensions', "color": 0}
for points in [[(3.68, 4.584), (3.68, 4.524), (3.5, 4.554)], [(9.32, 4.584), (9.32, 4.524), (9.5, 4.554)]]:
    blk.add_solid(points, dxfattribs=at)
at = {"layer": 'dimensions', "color": 0, "insert": (5.012, 4.554), "char_height": 0.1, "attachment_point": 5}
blk.add_mtext('\\A1;6.000', dxfattribs=at)
blk = doc.blocks.new('*D50')
at = {"layer": 'Defpoints', "color": 0}
for p in [(10.95, 2.25), (12.028, 2.25), (10.74, 1.95)]:
    blk.add_point(p, dxfattribs=at)
at = {"layer": 'dimensions', "color": 0, "lineweight": -2}
for p, q in [((12.028, 2.43), (12.028, 2.61)), ((11.012, 2.25), (12.208, 2.25)), ((10.803, 1.95), (12.208, 1.95)), ((12.028, 1.77), (12.028, 1.59))]:
    blk.add_line(p, q, dxfattribs=at)
at = {"layer": 'dimensions', "color": 0}
for points in [[(11.998, 2.43), (12.058, 2.43), (12.028, 2.25)], [(11.998, 1.77), (12.058, 1.77), (12.028, 1.95)]]:
    blk.add_solid(points, dxfattribs=at)
at = {"layer": 'dimensions', "color": 0, "insert": (12.028, 2.1), "char_height": 0.1, "attachment_point": 5}
blk.add_mtext('\\A1;0.300', dxfattribs=at)
blk = doc.blocks.new('*D51')
at = {"layer": 'Defpoints', "color": 0}
for p in [(10.95, 2.25), (11.25, 2.05), (11.544, 2.05)]:
    blk.add_point(p, dxfattribs=at)
at = {"layer": 'dimensions', "color": 0, "lineweight": -2}
for p, q in [((11.544, 2.43), (11.544, 2.61)), ((11.012, 2.25), (11.724, 2.25)), ((11.312, 2.05), (11.724, 2.05)), ((11.544, 1.87), (11.544, 1.69))]:
    blk.add_line(p, q, dxfattribs=at)
at = {"layer": 'dimensions', "color": 0}
for points in [[(11.514, 2.43), (11.574, 2.43), (11.544, 2.25)], [(11.514, 1.87), (11.574, 1.87), (11.544, 2.05)]]:
    blk.add_solid(points, dxfattribs=at)
at = {"layer": 'dimensions', "color": 0, "insert": (11.544, 2.15), "char_height": 0.1, "attachment_point": 5}
blk.add_mtext('\\A1;0.200', dxfattribs=at)
blk = doc.blocks.new('*D52')
at = {"layer": 'Defpoints', "color": 0}
for p in [(10.95, 2.502), (10.95, 2.25), (11.25, 2.05)]:
    blk.add_point(p, dxfattribs=at)
at = {"layer": 'dimensions', "color": 0, "lineweight": -2}
for p, q in [((10.95, 2.312), (10.95, 2.682)), ((11.25, 2.112), (11.25, 2.682)), ((10.77, 2.502), (10.59, 2.502)), ((11.43, 2.502), (11.61, 2.502))]:
    blk.add_line(p, q, dxfattribs=at)
at = {"layer": 'dimensions', "color": 0}
for points in [[(10.77, 2.532), (10.77, 2.472), (10.95, 2.502)], [(11.43, 2.532), (11.43, 2.472), (11.25, 2.502)]]:
    blk.add_solid(points, dxfattribs=at)
at = {"layer": 'dimensions', "color": 0, "insert": (11.1, 2.502), "char_height": 0.1, "attachment_point": 5}
blk.add_mtext('\\A1;.30', dxfattribs=at)
blk = doc.blocks.new('*D56')
at = {"layer": 'Defpoints', "color": 0}
for p in [(4.568, 1.681), (3.933, 1.332), (4.568, 1.332)]:
    blk.add_point(p, dxfattribs=at)
at = {"layer": 'dimensions', "color": 0, "lineweight": -2}
for p, q in [((3.933, 1.395), (3.933, 1.831)), ((4.568, 1.395), (4.568, 1.831)), ((3.933, 1.681), (3.752, 1.681)), ((4.388, 1.681), (4.112, 1.681))]:
    blk.add_line(p, q, dxfattribs=at)
at = {"layer": 'dimensions', "color": 0}
for points in [[(4.112, 1.711), (4.112, 1.651), (3.933, 1.681)], [(4.388, 1.711), (4.388, 1.651), (4.568, 1.681)]]:
    blk.add_solid(points, dxfattribs=at)
at = {"layer": 'dimensions', "color": 0, "insert": (3.511, 1.681), "char_height": 0.1, "attachment_point": 5}
blk.add_mtext('\\A1;0.635', dxfattribs=at)
blk = doc.blocks.new('*D57')
at = {"layer": 'Defpoints', "color": 0}
for p in [(1, 3.84), (1, 2.25), (4.25, 1.482)]:
    blk.add_point(p, dxfattribs=at)
at = {"layer": 'dimensions', "color": 0, "lineweight": -2}
for p, q in [((1, 2.312), (1, 4.02)), ((4.25, 1.545), (4.25, 4.02)), ((1.18, 3.84), (2.343, 3.84)), ((4.07, 3.84), (2.907, 3.84))]:
    blk.add_line(p, q, dxfattribs=at)
at = {"layer": 'dimensions', "color": 0}
for points in [[(1.18, 3.87), (1.18, 3.81), (1, 3.84)], [(4.07, 3.87), (4.07, 3.81), (4.25, 3.84)]]:
    blk.add_solid(points, dxfattribs=at)
at = {"layer": 'dimensions', "color": 0, "insert": (2.625, 3.84), "char_height": 0.1, "attachment_point": 5}
blk.add_mtext('\\A1;3.250', dxfattribs=at)
blk = doc.blocks.new('*D58')
at = {"layer": 'Defpoints', "color": 0}
for p in [(3.973, 1.274), (3.995, 1.332)]:
    blk.add_point(p, dxfattribs=at)
at = {"layer": 'dimensions', "color": 0, "lineweight": -2}
for p, q in [((3.995, 1.242), (3.995, 1.422)), ((3.905, 1.332), (4.085, 1.332)), ((3.753, 0.676), (3.911, 1.105)), ((3.523, 0.676), (3.753, 0.676))]:
    blk.add_line(p, q, dxfattribs=at)
at = {"layer": 'dimensions', "color": 0}
blk.add_solid([(3.883, 1.115), (3.939, 1.094), (3.973, 1.274)], dxfattribs=at)
at = {"layer": 'dimensions', "color": 0, "insert": (3.2, 0.676), "char_height": 0.1, "attachment_point": 5}
blk.add_mtext('\\A1;R0.063', dxfattribs=at)
blk = doc.blocks.new('*D59')
at = {"layer": 'Defpoints', "color": 0}
for p in [(4.25, 1.332), (4.25, 0.857), (5.007, 0.857)]:
    blk.add_point(p, dxfattribs=at)
at = {"layer": 'dimensions', "color": 0, "lineweight": -2}
for p, q in [((5.007, 1.512), (5.007, 1.692)), ((4.312, 1.332), (5.187, 1.332)), ((4.312, 0.857), (5.187, 0.857)), ((5.007, 0.677), (5.007, 0.497))]:
    blk.add_line(p, q, dxfattribs=at)
at = {"layer": 'dimensions', "color": 0}
for points in [[(4.977, 1.512), (5.037, 1.512), (5.007, 1.332)], [(4.977, 0.677), (5.037, 0.677), (5.007, 0.857)]]:
    blk.add_solid(points, dxfattribs=at)
at = {"layer": 'dimensions', "color": 0, "insert": (5.007, 1.095), "char_height": 0.1, "attachment_point": 5}
blk.add_mtext('\\A1;0.475', dxfattribs=at)
blk = doc.blocks.new('*D60')
at = {"layer": 'Defpoints', "color": 0}
for p in [(5.653, 1.594), (5.587, 1.406)]:
    blk.add_point(p, dxfattribs=at)
at = {"layer": 'dimensions', "color": 0, "lineweight": -2}
for p, q in [((5.62, 1.41), (5.62, 1.59)), ((5.53, 1.5), (5.71, 1.5)), ((5.19, 0.27), (5.528, 1.236)), ((4.968, 0.27), (5.19, 0.27))]:
    blk.add_line(p, q, dxfattribs=at)
at = {"layer": 'dimensions', "color": 0}
blk.add_solid([(5.499, 1.246), (5.556, 1.226), (5.587, 1.406)], dxfattribs=at)
at = {"layer": 'dimensions', "color": 0, "insert": (4.653, 0.27), "char_height": 0.1, "attachment_point": 5}
blk.add_mtext('\\A1;∅0.200', dxfattribs=at)
blk = doc.blocks.new('*D61')
at = {"layer": 'Defpoints', "color": 0}
for p in [(14.4, 2.858), (13.45, 2.25), (14.4, 2.25)]:
    blk.add_point(p, dxfattribs=at)
at = {"layer": 'dimensions', "color": 0, "lineweight": -2}
for p, q in [((13.45, 2.312), (13.45, 3.038)), ((14.4, 2.312), (14.4, 3.038)), ((13.63, 2.858), (13.652, 2.858)), ((14.22, 2.858), (14.198, 2.858))]:
    blk.add_line(p, q, dxfattribs=at)
at = {"layer": 'dimensions', "color": 0}
for points in [[(13.63, 2.888), (13.63, 2.828), (13.45, 2.858)], [(14.22, 2.888), (14.22, 2.828), (14.4, 2.858)]]:
    blk.add_solid(points, dxfattribs=at)
at = {"layer": 'dimensions', "color": 0, "insert": (13.925, 2.858), "char_height": 0.1, "attachment_point": 5}
blk.add_mtext('\\A1;0.950', dxfattribs=at)
blk = doc.blocks.new('*D62')
at = {"layer": 'Defpoints', "color": 0}
for p in [(13.25, 2.467), (13.25, 2.25), (13.45, 2.25)]:
    blk.add_point(p, dxfattribs=at)
at = {"layer": 'dimensions', "color": 0, "lineweight": -2}
for p, q in [((13.25, 2.312), (13.25, 2.647)), ((13.45, 2.312), (13.45, 2.647)), ((13.07, 2.467), (12.89, 2.467)), ((13.63, 2.467), (13.852, 2.467))]:
    blk.add_line(p, q, dxfattribs=at)
at = {"layer": 'dimensions', "color": 0}
for points in [[(13.07, 2.497), (13.07, 2.437), (13.25, 2.467)], [(13.63, 2.497), (13.63, 2.437), (13.45, 2.467)]]:
    blk.add_solid(points, dxfattribs=at)
at = {"layer": 'dimensions', "color": 0, "insert": (14.117, 2.467), "char_height": 0.1, "attachment_point": 5}
blk.add_mtext('\\A1;0.200', dxfattribs=at)
blk = doc.blocks.new('*D63')
at = {"layer": 'Defpoints', "color": 0}
for p in [(13.25, 0.55), (14.6, 0.55), (14.6, -0.056)]:
    blk.add_point(p, dxfattribs=at)
at = {"layer": 'dimensions', "color": 0, "lineweight": -2}
for p, q in [((13.25, 0.487), (13.25, -0.236)), ((14.6, 0.487), (14.6, -0.236)), ((13.43, -0.056), (13.66, -0.056)), ((14.42, -0.056), (14.19, -0.056))]:
    blk.add_line(p, q, dxfattribs=at)
at = {"layer": 'dimensions', "color": 0}
for points in [[(13.43, -0.026), (13.43, -0.086), (13.25, -0.056)], [(14.42, -0.026), (14.42, -0.086), (14.6, -0.056)]]:
    blk.add_solid(points, dxfattribs=at)
at = {"layer": 'dimensions', "color": 0, "insert": (13.925, -0.056), "char_height": 0.1, "attachment_point": 5}
blk.add_mtext('\\A1;1.350', dxfattribs=at)
blk = doc.blocks.new('*D64')
at = {"layer": 'Defpoints', "color": 0}
for p in [(13.3, 0.55), (14.55, 0.55), (14.55, 0.233)]:
    blk.add_point(p, dxfattribs=at)
at = {"layer": 'dimensions', "color": 0, "lineweight": -2}
for p, q in [((13.3, 0.487), (13.3, 0.053)), ((14.55, 0.487), (14.55, 0.053)), ((13.48, 0.233), (13.66, 0.233)), ((14.37, 0.233), (14.19, 0.233))]:
    blk.add_line(p, q, dxfattribs=at)
at = {"layer": 'dimensions', "color": 0}
for points in [[(13.48, 0.263), (13.48, 0.203), (13.3, 0.233)], [(14.37, 0.263), (14.37, 0.203), (14.55, 0.233)]]:
    blk.add_solid(points, dxfattribs=at)
at = {"layer": 'dimensions', "color": 0, "insert": (13.925, 0.233), "char_height": 0.1, "attachment_point": 5}
blk.add_mtext('\\A1;1.250', dxfattribs=at)
blk = doc.blocks.new('*D67')
at = {"layer": 'Defpoints', "color": 0}
for p in [(6.335, 1.287), (6.365, 1.013)]:
    blk.add_point(p, dxfattribs=at)
at = {"layer": 'dimensions', "color": 0, "lineweight": -2}
for p, q in [((6.26, 1.15), (6.44, 1.15)), ((6.35, 1.06), (6.35, 1.24)), ((6.461, 0.116), (6.384, 0.834)), ((6.909, 0.116), (6.461, 0.116))]:
    blk.add_line(p, q, dxfattribs=at)
at = {"layer": 'dimensions', "color": 0}
blk.add_solid([(6.414, 0.837), (6.354, 0.831), (6.365, 1.013)], dxfattribs=at)
at = {"layer": 'dimensions', "color": 0, "insert": (7.241, 0.116), "char_height": 0.1, "attachment_point": 5}
blk.add_mtext('\\A1;∅0.276', dxfattribs=at)
blk = doc.blocks.new('*D68')
at = {"layer": 'Defpoints', "color": 0}
for p in [(8.802, 1.798), (8.798, 1.602)]:
    blk.add_point(p, dxfattribs=at)
at = {"layer": 'dimensions', "color": 0, "lineweight": -2}
for p, q in [((8.8, 1.61), (8.8, 1.79)), ((8.71, 1.7), (8.89, 1.7)), ((8.775, 0.476), (8.794, 1.422)), ((8.34, 0.476), (8.775, 0.476))]:
    blk.add_line(p, q, dxfattribs=at)
at = {"layer": 'dimensions', "color": 0}
blk.add_solid([(8.764, 1.422), (8.824, 1.421), (8.798, 1.602)], dxfattribs=at)
at = {"layer": 'dimensions', "color": 0, "insert": (8.025, 0.476), "char_height": 0.1, "attachment_point": 5}
blk.add_mtext('\\A1;∅0.197', dxfattribs=at)
blk = doc.blocks.new('*D70')
at = {"layer": 'Defpoints', "color": 0, "linetype": 'ACAD_ISO03W100'}
for p in [(11.25, 6.42), (1, 2.25), (11.25, 2.05)]:
    blk.add_point(p, dxfattribs=at)
at = {"layer": 'dimensions', "color": 0, "linetype": 'ACAD_ISO03W100', "lineweight": -2}
for p, q in [((1, 2.312), (1, 6.6)), ((11.25, 2.112), (11.25, 6.6)), ((1.18, 6.42), (5.818, 6.42)), ((11.07, 6.42), (6.432, 6.42))]:
    blk.add_line(p, q, dxfattribs=at)
at = {"layer": 'dimensions', "color": 0, "linetype": 'ACAD_ISO03W100'}
for points in [[(1.18, 6.45), (1.18, 6.39), (1, 6.42)], [(11.07, 6.45), (11.07, 6.39), (11.25, 6.42)]]:
    blk.add_solid(points, dxfattribs=at)
at = {"layer": 'dimensions', "color": 0, "linetype": 'ACAD_ISO03W100', "insert": (6.125, 6.42), "char_height": 0.1, "attachment_point": 5}
blk.add_mtext('\\A1;10.250', dxfattribs=at)

msp = doc.modelspace()

# ---------------------------------------------------------------- hatches: boundary and pattern name
at = {"layer": 'lines'}
h = msp.add_hatch(dxfattribs=at)
h.set_pattern_fill('STEEL', color=256, angle=45, style=0)
h.set_pattern_definition([(90, (0, 0), (-0.125, 3e-17), []), (90, (-0.0442, 0.0442), (-0.125, 3e-17), [])])
edge = h.paths.add_edge_path()
edge.add_line((3.5, 2.2), (9.5, 2.2))
edge.add_line((10.95, 2.25), (1, 2.25))
h = msp.add_hatch(color=1, dxfattribs=at)
h.paths.add_polyline_path([(14.55, 0.55), (14.55, 0.615), (14.485, 0.55)])
h.paths.add_polyline_path([(13.365, 0.55), (13.3, 0.615), (13.3, 0.55)])

# ---------------------------------------------------------------- linework, layer by layer
at = {"layer": 'dimensions'}
for p, q in [((10.65, 1.86), (10.65, 2.04)), ((10.56, 1.95), (10.74, 1.95)), ((8.8, 1.61), (8.8, 1.79)), ((8.71, 1.7), (8.89, 1.7)), ((4.25, 1.5448), (4.25, 1.3323)), ((5.62, 1.41), (5.62, 1.59)), ((9.63, 1.36), (9.63, 1.54)), ((3.995, 1.2423), (3.995, 1.4223)), ((4.505, 1.2423), (4.505, 1.4223)), ((5.53, 1.5), (5.71, 1.5)), ((9.54, 1.45), (9.72, 1.45)), ((3.905, 1.3323), (4.085, 1.3323)), ((4.085, 1.3323), (4.415, 1.3323)), ((4.415, 1.3323), (4.595, 1.3323)), ((6.26, 1.15), (6.44, 1.15)), ((6.35, 1.06), (6.35, 1.24)), ((7.9, 0.7315), (7.9, 0.96)), ((7.762, 0.87), (7.99, 0.87))]:
    msp.add_line(p, q, dxfattribs=at)
at = {"layer": 'lines', "linetype": 'ByBlock'}
msp.add_line((1, 2.25), (10.95, 2.25), dxfattribs=at)
at = {"layer": 'lines', "color": 1}
for p, q in [((3.5, 2.25), (3.5, 2.2)), ((3.5, 2.2), (9.5, 2.2)), ((9.5, 2.25), (9.5, 2.2)), ((10.95, 2.25), (10.95, 2.05)), ((13.25, 0.55), (13.25, 2.25)), ((13.25, 2.25), (13.45, 2.25)), ((13.3, 2.2), (13.45, 2.2)), ((13.3, 0.55), (13.3, 2.2)), ((13.45, 2.25), (13.45, 2.2)), ((14.6, 2.25), (14.4, 2.25)), ((14.4, 2.25), (14.4, 2.2)), ((14.4, 2.2), (14.55, 2.2)), ((14.55, 0.55), (14.55, 2.2)), ((14.6, 0.55), (14.6, 2.25)), ((11.25, 2.05), (10.95, 2.05)), ((11.25, 2.05), (11.25, 0.55)), ((3.995, 1.4823), (4.505, 1.4823)), ((3.995, 1.3948), (4.505, 1.3948)), ((3.995, 1.2698), (4.505, 1.2698)), ((3.995, 1.1823), (4.505, 1.1823)), ((11.25, 0.55), (1, 1)), ((13.3, 1), (14.55, 1)), ((11.25, 0.55), (11.25, 0.675)), ((14.55, 0.675), (13.3, 0.675)), ((13.25, 0.55), (13.3, 0.55)), ((13.3, 0.615), (13.365, 0.55)), ((13.3, 0.55), (14.55, 0.55)), ((14.485, 0.55), (14.55, 0.615)), ((14.6, 0.55), (14.55, 0.55))]:
    msp.add_line(p, q, dxfattribs=at)
for centre, radius in [((10.65, 1.95), 0.0825), ((8.8, 1.7), 0.0985), ((5.62, 1.5), 0.1), ((9.63, 1.45), 0.0825), ((6.35, 1.15), 0.138), ((7.9, 0.87), 0.138)]:
    msp.add_circle(centre, radius, dxfattribs=at)
for centre, radius, start, end in [((3.995, 1.3323), 0.15, 90, 270), ((3.995, 1.3323), 0.0625, 90, 180), ((4.505, 1.3323), 0.15, 270, 90), ((4.505, 1.3323), 0.0625, 0, 90), ((3.995, 1.3323), 0.0625, 180, 270), ((4.505, 1.3323), 0.0625, 270, 0)]:
    msp.add_arc(centre, radius, start, end, dxfattribs=at)

# ---------------------------------------------------------------- texts
at = {"layer": 'dimensions'}
msp.add_text('(7mm)', height=0.1, dxfattribs=at).set_placement((7.0422, -0.1001))
at = {"layer": 'dimensions', "char_height": 0.1, "attachment_point": 1}
for s, insert, width in [('Top rail location. Rail is .20" wide', (3.626, 4.3812), 1.9884), ('Rear receiver view (assembled)', (13.5384, 1.9138), 0.8743), ('File to fit', (15.1726, 1.7717), 1.006781), ('Stamp .110 deep', (2.8714, 0.5132), 0.998118), ('(5mm)', (7.8809, 0.3749), 0.4842), ('File edges of bottom flat at 45 degrees, halfway through material and fill with weld.', (15.1732, 0.4785), 0.9047)]:
    msp.add_mtext(s, dxfattribs=dict(at, insert=insert, width=width))

# ---------------------------------------------------------------- dimensions: what is measured, and where the dimension line sits
at = {"layer": 'dimensions', "linetype": 'ACAD_ISO03W100'}
dim = msp.add_linear_dim(base=(11.25, 6.4198), p1=(1, 2.25), p2=(11.25, 2.05), dimstyle='Standard', override={"dimtxt": 0.1}, dxfattribs=at)
dim.commit()
dim.dimension.update_dxf_attribs({"geometry": '*D70', "text_midpoint": (6.125, 6.4198)})
at = {"layer": 'dimensions'}
for base, p1, p2, override, picture, middle in [((11.25, 5.8728), (5.62, 1.5), (11.25, 2.25), {"dimtxt": 0.1}, '*D23', (8.5029, 5.8728)), ((6.35, 5.2462), (11.25, 2.25), (6.35, 1.15), {"dimtxt": 0.1}, '*D24', (8.7379, 5.2462)), ((1, 4.551), (3.5, 2.25), (1, 2.25), {"dimtxt": 0.1}, '*D48', (2.25, 4.551)), ((3.5, 4.5538), (9.5, 2.25), (3.5, 2.3125), {"dimtxt": 0.1}, '*D49', (5.0121, 4.5538)), ((7.9, 4.1254), (11.25, 2.25), (7.9, 0.87), {"dimtxt": 0.1}, '*D25', (9.939, 4.1254)), ((1, 3.84), (4.25, 1.4823), (1, 2.25), {"dimtxt": 0.1}, '*D57', (2.625, 3.84)), ((8.8, 3.6401), (11.25, 2.25), (8.8, 1.7), {"dimtxt": 0.1}, '*D26', (10.025, 3.6401)), ((9.63, 3.1877), (11.25, 2.25), (9.63, 1.45), {"dimtxt": 0.1}, '*D27', (10.44, 3.1877)), ((10.65, 2.8604), (11.25, 2.25), (10.65, 1.95), {"dimtxt": 0.1}, '*D33', (11.0126, 2.8604)), ((14.4, 2.8578), (13.45, 2.25), (14.4, 2.25), {"dimtxt": 0.1}, '*D61', (13.925, 2.8578)), ((13.25, 2.4666), (13.45, 2.25), (13.25, 2.25), {"dimtxt": 0.1}, '*D62', (14.1167, 2.4666)), ((4.5675, 1.6814), (3.9325, 1.3323), (4.5675, 1.3323), {"dimtxt": 0.1, "dimexe": 0.15, "dimgap": 0.05}, '*D56', (3.5108, 1.6814))]:
    dim = msp.add_linear_dim(base=base, p1=p1, p2=p2, dimstyle='Standard', override=override, dxfattribs=at)
    dim.commit()
    dim.dimension.update_dxf_attribs({"geometry": picture, "text_midpoint": middle, "dimtype": 160})
dim = msp.add_linear_dim(base=(10.95, 2.5024), p1=(11.25, 2.05), p2=(10.95, 2.25), text='.30', dimstyle='Standard', override={"dimtxt": 0.1}, dxfattribs=at)
dim.commit()
dim.dimension.update_dxf_attribs({"geometry": '*D52', "text_midpoint": (11.1, 2.5024), "dimtype": 160})
for base, p1, p2, picture, middle in [((8.9775, 2.25), (8.8, 1.7), (8.8, 2.25), '*D29', (8.9775, 2.02)), ((12.0277, 2.25), (10.74, 1.95), (10.95, 2.25), '*D50', (12.0277, 2.1)), ((11.5436, 2.05), (10.95, 2.25), (11.25, 2.05), '*D51', (11.5436, 2.15)), ((5.3622, 2.25), (5.62, 1.5), (5.62, 2.25), '*D30', (5.3622, 1.856)), ((6.8483, 2.25), (6.35, 1.15), (6.35, 2.25), '*D31', (6.8483, 1.6919)), ((8.0977, 2.25), (7.9, 0.87), (7.9, 2.25), '*D32', (8.0977, 1.56)), ((9.9605, 2.25), (9.63, 1.45), (9.63, 2.25), '*D28', (9.9605, 1.8443)), ((5.0074, 0.8573), (4.25, 1.3323), (4.25, 0.8573), '*D59', (5.0074, 1.0948))]:
    dim = msp.add_linear_dim(base=base, p1=p1, p2=p2, angle=90, dimstyle='Standard', override={"dimtxt": 0.1}, dxfattribs=at)
    dim.commit()
    dim.dimension.update_dxf_attribs({"geometry": picture, "text_midpoint": middle, "dimtype": 160})
dim = msp.add_linear_dim(base=(12.3164, 0.55), p1=(11.25, 2.25), p2=(11.25, 0.55), angle=90, dimstyle='Standard', override={"dimtxt": 0.1}, dxfattribs=at)
dim.commit()
dim.dimension.update_dxf_attribs({"geometry": '*D34', "text_midpoint": (12.3164, 1.4)})
for p1, p2, picture, middle in [((8.802, 1.7985), (8.798, 1.6015), '*D68', (8.0246, 0.4756)), ((5.653, 1.5944), (5.587, 1.4056), '*D60', (4.6531, 0.27)), ((9.6331, 1.5324), (9.6269, 1.3676), '*D47', (8.8285, 0.0879)), ((6.3353, 1.2872), (6.3647, 1.0128), '*D67', (7.2407, 0.1159))]:
    dim = msp.add_diameter_dim_2p(p1=p1, p2=p2, dimstyle='Standard', override={"dimtxt": 0.1}, dxfattribs=at)
    dim.commit()
    dim.dimension.update_dxf_attribs({"geometry": picture, "text_midpoint": middle, "dimtype": 163})
dim = msp.add_radius_dim(center=(3.995, 1.3323), mpoint=(3.9734, 1.2737), dimstyle='Standard', override={"dimtxt": 0.1}, dxfattribs=at)
dim.commit()
dim.dimension.update_dxf_attribs({"geometry": '*D58', "text_midpoint": (3.1995, 0.6759), "dimtype": 164})
for base, p1, p2, picture, middle in [((14.6, -0.0565), (13.25, 0.55), (14.6, 0.55), '*D63', (13.925, -0.0565)), ((14.55, 0.2328), (13.3, 0.55), (14.55, 0.55), '*D64', (13.925, 0.2328))]:
    dim = msp.add_linear_dim(base=base, p1=p1, p2=p2, dimstyle='Standard', override={"dimtxt": 0.1}, dxfattribs=at)
    dim.commit()
    dim.dimension.update_dxf_attribs({"geometry": picture, "text_midpoint": middle})

# ---------------------------------------------------------------- leaders
for points in [[(4.9258, 2.25), (4.8025, 4.1162), (4.6883, 4.1162)], [(13.45, 2.2), (14.9262, 1.7247)], [(14.4, 2.2), (14.9262, 1.7247), (15.0468, 1.7247)], [(10.65, 1.8675), (9.5785, 0.0879)], [(7.7615, 0.87), (6.4607, 0.1159)], [(13.365, 0.55), (14.9764, 0.3878)], [(14.55, 0.55), (14.9764, 0.3878), (15.0899, 0.3878)]]:
    msp.add_leader(points, dimstyle='Standard', override={"dimgap": 0.09, "dimtad": 0}, dxfattribs=at)

doc.saveas('drawing.dxf')
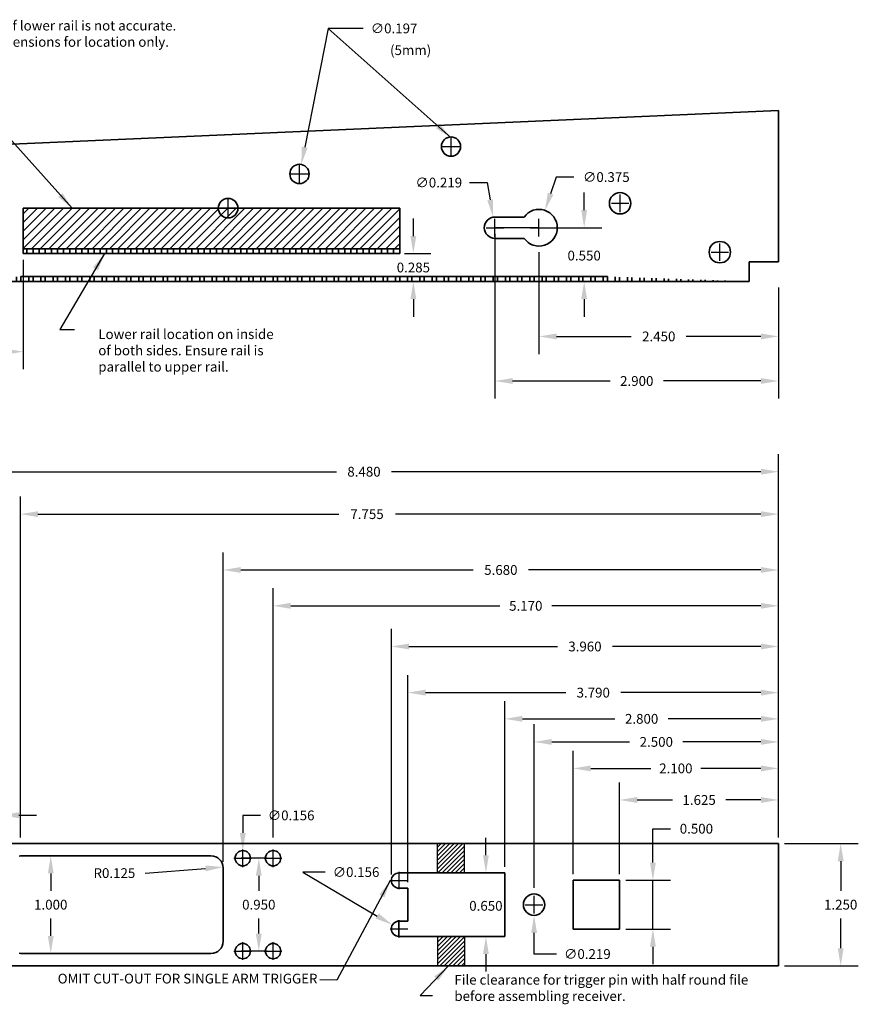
# Model space of a CAD drawing. Units: inches. Extents: x -3.6 to 16.1, y -0.6 to 17.2.
# Drawn here: x 3.5 to 12.1, y 7.1 to 17.2 of the extents above; entities that cross this region are included whole.
import ezdxf

# ---------------------------------------------------------------- set-up
doc = ezdxf.new("R2010")
doc.units = ezdxf.units.IN
doc.header["$MEASUREMENT"] = 0
doc.linetypes.add('ACAD_ISO03W100', pattern=[30, 12, -18])
doc.layers.add('dimensions', color=7, linetype='Continuous')
doc.layers.add('lines', color=1, linetype='Continuous', lineweight=35)
doc.dimstyles.get("Standard").update_dxf_attribs({"dimtxt": 0.18, "dimasz": 0.18, "dimexe": 0.18, "dimexo": 0.0625, "dimgap": 0.09, "dimtad": 0, "dimtih": 1, "dimtoh": 1, "dimdec": 3, "dimzin": 0, "dimdsep": 46, "dimtxsty": 'Standard', "dimcen": 0.09, "dimadec": 0, "dimazin": 0, "dimtfac": 1, "dimtdec": 3, "dimtofl": 0, "dimtmove": 0, "dimatfit": 3, "dimfxl": 0, "dimtolj": 1, "dimtzin": 0, "dimarcsym": 0})
pattern_1 = [(45, (0, 0.729907), (-0.02209709, 0.02209709), [])]

# ---------------------------------------------------------------- blocks, each defined once
blk = doc.blocks.new('*D6')
at = {"layer": 'Defpoints', "color": 0}
for p in [(5.445, 8.5), (5.57, 8.51)]:
    blk.add_point(p, dxfattribs=at)
at = {"layer": 'dimensions', "color": 0, "lineweight": -2}
blk.add_line((4.772, 8.448), (5.39, 8.496), dxfattribs=at)
at = {"layer": 'dimensions', "color": 0}
blk.add_solid([(5.388, 8.526), (5.392, 8.466), (5.57, 8.51)], dxfattribs=at)
at = {"layer": 'dimensions', "color": 0, "insert": (4.457, 8.448), "char_height": 0.1, "attachment_point": 5}
blk.add_mtext('\\A1;R0.125', dxfattribs=at)
blk = doc.blocks.new('*D7')
at = {"layer": 'Defpoints', "color": 0}
for p in [(2.77, 12.554), (2.77, 8.75), (11.25, 8.75)]:
    blk.add_point(p, dxfattribs=at)
at = {"layer": 'dimensions', "color": 0, "lineweight": -2}
for p, q in [((2.77, 8.812), (2.77, 12.734)), ((11.25, 8.812), (11.25, 12.734)), ((2.95, 12.554), (6.728, 12.554)), ((11.07, 12.554), (7.292, 12.554))]:
    blk.add_line(p, q, dxfattribs=at)
at = {"layer": 'dimensions', "color": 0}
for points in [[(2.95, 12.584), (2.95, 12.524), (2.77, 12.554)], [(11.07, 12.584), (11.07, 12.524), (11.25, 12.554)]]:
    blk.add_solid(points, dxfattribs=at)
at = {"layer": 'dimensions', "color": 0, "insert": (7.01, 12.554), "char_height": 0.1, "attachment_point": 5}
blk.add_mtext('\\A1;8.480', dxfattribs=at)
blk = doc.blocks.new('*D8')
at = {"layer": 'Defpoints', "color": 0}
for p in [(11.25, 12.12), (3.495, 8.75), (11.25, 8.75)]:
    blk.add_point(p, dxfattribs=at)
at = {"layer": 'dimensions', "color": 0, "lineweight": -2}
for p, q in [((3.495, 8.812), (3.495, 12.3)), ((11.25, 8.812), (11.25, 12.3)), ((3.675, 12.12), (6.751, 12.12)), ((11.07, 12.12), (7.331, 12.12))]:
    blk.add_line(p, q, dxfattribs=at)
at = {"layer": 'dimensions', "color": 0}
for points in [[(3.675, 12.15), (3.675, 12.09), (3.495, 12.12)], [(11.07, 12.15), (11.07, 12.09), (11.25, 12.12)]]:
    blk.add_solid(points, dxfattribs=at)
at = {"layer": 'dimensions', "color": 0, "insert": (7.041, 12.12), "char_height": 0.1, "attachment_point": 5}
blk.add_mtext('\\A1;7.755', dxfattribs=at)
blk = doc.blocks.new('*D9')
at = {"layer": 'Defpoints', "color": 0}
for p in [(3.51, 8.625), (3.51, 7.625), (3.806, 7.625)]:
    blk.add_point(p, dxfattribs=at)
at = {"layer": 'dimensions', "color": 0, "lineweight": -2}
for p, q in [((3.572, 8.625), (3.986, 8.625)), ((3.806, 8.445), (3.806, 8.265)), ((3.806, 7.805), (3.806, 7.985)), ((3.572, 7.625), (3.986, 7.625))]:
    blk.add_line(p, q, dxfattribs=at)
at = {"layer": 'dimensions', "color": 0}
for points in [[(3.776, 8.445), (3.836, 8.445), (3.806, 8.625)], [(3.776, 7.805), (3.836, 7.805), (3.806, 7.625)]]:
    blk.add_solid(points, dxfattribs=at)
at = {"layer": 'dimensions', "color": 0, "insert": (3.806, 8.125), "char_height": 0.1, "attachment_point": 5}
blk.add_mtext('\\A1;1.000', dxfattribs=at)
blk = doc.blocks.new('*D17')
at = {"layer": 'Defpoints', "color": 0}
for p in [(3.3, 9.04), (2.77, 8.575), (3.3, 8.575)]:
    blk.add_point(p, dxfattribs=at)
at = {"layer": 'dimensions', "color": 0, "lineweight": -2}
for p, q in [((2.77, 8.638), (2.77, 9.22)), ((3.3, 8.638), (3.3, 9.22)), ((2.59, 9.04), (2.41, 9.04)), ((3.48, 9.04), (3.66, 9.04))]:
    blk.add_line(p, q, dxfattribs=at)
at = {"layer": 'dimensions', "color": 0}
for points in [[(2.59, 9.07), (2.59, 9.01), (2.77, 9.04)], [(3.48, 9.07), (3.48, 9.01), (3.3, 9.04)]]:
    blk.add_solid(points, dxfattribs=at)
at = {"layer": 'dimensions', "color": 0, "insert": (3.035, 9.04), "char_height": 0.1, "attachment_point": 5}
blk.add_mtext('\\A1;0.530', dxfattribs=at)
blk = doc.blocks.new('*D18')
at = {"layer": 'Defpoints', "color": 0}
for p in [(6.08, 8.6), (5.934, 7.65), (6.08, 7.65)]:
    blk.add_point(p, dxfattribs=at)
at = {"layer": 'dimensions', "color": 0, "lineweight": -2}
for p, q in [((6.018, 8.6), (5.754, 8.6)), ((5.934, 8.42), (5.934, 8.265)), ((5.934, 7.83), (5.934, 7.985)), ((6.018, 7.65), (5.754, 7.65))]:
    blk.add_line(p, q, dxfattribs=at)
at = {"layer": 'dimensions', "color": 0}
for points in [[(5.904, 8.42), (5.964, 8.42), (5.934, 8.6)], [(5.904, 7.83), (5.964, 7.83), (5.934, 7.65)]]:
    blk.add_solid(points, dxfattribs=at)
at = {"layer": 'dimensions', "color": 0, "insert": (5.934, 8.125), "char_height": 0.1, "attachment_point": 5}
blk.add_mtext('\\A1;0.950', dxfattribs=at)
blk = doc.blocks.new('*D19')
at = {"layer": 'Defpoints', "color": 0}
for p in [(8.45, 8.45), (8.257, 7.8), (8.45, 7.8)]:
    blk.add_point(p, dxfattribs=at)
at = {"layer": 'dimensions', "color": 0, "lineweight": -2}
for p, q in [((8.257, 8.63), (8.257, 8.81)), ((8.387, 8.45), (8.077, 8.45)), ((8.387, 7.8), (8.077, 7.8)), ((8.257, 7.62), (8.257, 7.44))]:
    blk.add_line(p, q, dxfattribs=at)
at = {"layer": 'dimensions', "color": 0}
for points in [[(8.227, 8.63), (8.287, 8.63), (8.257, 8.45)], [(8.227, 7.62), (8.287, 7.62), (8.257, 7.8)]]:
    blk.add_solid(points, dxfattribs=at)
at = {"layer": 'dimensions', "color": 0, "insert": (8.257, 8.113), "char_height": 0.1, "attachment_point": 5}
blk.add_mtext('\\A1;0.650', dxfattribs=at)
blk = doc.blocks.new('*D20')
at = {"layer": 'Defpoints', "color": 0}
for p in [(9.625, 8.375), (9.625, 7.875), (9.965, 7.875)]:
    blk.add_point(p, dxfattribs=at)
at = {"layer": 'dimensions', "color": 0, "lineweight": -2}
for p, q in [((9.965, 8.555), (9.965, 8.902)), ((9.965, 8.902), (10.145, 8.902)), ((9.688, 8.375), (10.145, 8.375)), ((9.965, 7.875), (9.965, 8.375)), ((9.688, 7.875), (10.145, 7.875)), ((9.965, 7.695), (9.965, 7.515))]:
    blk.add_line(p, q, dxfattribs=at)
at = {"layer": 'dimensions', "color": 0}
for points in [[(9.935, 8.555), (9.995, 8.555), (9.965, 8.375)], [(9.935, 7.695), (9.995, 7.695), (9.965, 7.875)]]:
    blk.add_solid(points, dxfattribs=at)
at = {"layer": 'dimensions', "color": 0, "insert": (10.41, 8.902), "char_height": 0.1, "attachment_point": 5}
blk.add_mtext('\\A1;0.500', dxfattribs=at)
blk = doc.blocks.new('*D21')
at = {"layer": 'Defpoints', "color": 0}
for p in [(11.25, 8.75), (11.25, 7.5), (11.886, 7.5)]:
    blk.add_point(p, dxfattribs=at)
at = {"layer": 'dimensions', "color": 0, "lineweight": -2}
for p, q in [((11.312, 8.75), (12.066, 8.75)), ((11.886, 8.57), (11.886, 8.265)), ((11.886, 7.68), (11.886, 7.985)), ((11.312, 7.5), (12.066, 7.5))]:
    blk.add_line(p, q, dxfattribs=at)
at = {"layer": 'dimensions', "color": 0}
for points in [[(11.856, 8.57), (11.916, 8.57), (11.886, 8.75)], [(11.856, 7.68), (11.916, 7.68), (11.886, 7.5)]]:
    blk.add_solid(points, dxfattribs=at)
at = {"layer": 'dimensions', "color": 0, "insert": (11.886, 8.125), "char_height": 0.1, "attachment_point": 5}
blk.add_mtext('\\A1;1.250', dxfattribs=at)
blk = doc.blocks.new('*D22')
at = {"layer": 'Defpoints', "color": 0}
for p in [(8.75, 8.2344), (8.75, 8.0156)]:
    blk.add_point(p, dxfattribs=at)
at = {"layer": 'dimensions', "color": 0, "lineweight": -2}
for p, q in [((8.75, 8.035), (8.75, 8.215)), ((8.66, 8.125), (8.84, 8.125)), ((8.75, 7.62), (8.75, 7.8356)), ((8.98, 7.62), (8.75, 7.62))]:
    blk.add_line(p, q, dxfattribs=at)
at = {"layer": 'dimensions', "color": 0}
blk.add_solid([(8.72, 7.8356), (8.78, 7.8356), (8.75, 8.0156)], dxfattribs=at)
at = {"layer": 'dimensions', "color": 0, "insert": (9.295, 7.62), "char_height": 0.1, "attachment_point": 5}
blk.add_mtext('\\A1;∅0.219', dxfattribs=at)
blk = doc.blocks.new('*D35')
at = {"layer": 'Defpoints', "color": 0}
for p in [(11.25, 11.549), (11.25, 8.75), (5.57, 8.5)]:
    blk.add_point(p, dxfattribs=at)
at = {"layer": 'dimensions', "color": 0, "lineweight": -2}
for p, q in [((5.57, 8.562), (5.57, 11.729)), ((11.25, 8.812), (11.25, 11.729)), ((5.75, 11.549), (8.128, 11.549)), ((11.07, 11.549), (8.692, 11.549))]:
    blk.add_line(p, q, dxfattribs=at)
at = {"layer": 'dimensions', "color": 0}
for points in [[(5.75, 11.579), (5.75, 11.519), (5.57, 11.549)], [(11.07, 11.579), (11.07, 11.519), (11.25, 11.549)]]:
    blk.add_solid(points, dxfattribs=at)
at = {"layer": 'dimensions', "color": 0, "insert": (8.41, 11.549), "char_height": 0.1, "attachment_point": 5}
blk.add_mtext('\\A1;5.680', dxfattribs=at)
blk = doc.blocks.new('*D36')
at = {"layer": 'Defpoints', "color": 0}
for p in [(8.75, 9.79), (11.25, 8.75), (8.75, 8.234)]:
    blk.add_point(p, dxfattribs=at)
at = {"layer": 'dimensions', "color": 0, "lineweight": -2}
for p, q in [((8.75, 8.297), (8.75, 9.97)), ((11.25, 8.812), (11.25, 9.97)), ((8.93, 9.79), (9.727, 9.79)), ((11.07, 9.79), (10.273, 9.79))]:
    blk.add_line(p, q, dxfattribs=at)
at = {"layer": 'dimensions', "color": 0}
for points in [[(8.93, 9.82), (8.93, 9.76), (8.75, 9.79)], [(11.07, 9.82), (11.07, 9.76), (11.25, 9.79)]]:
    blk.add_solid(points, dxfattribs=at)
at = {"layer": 'dimensions', "color": 0, "insert": (10, 9.79), "char_height": 0.1, "attachment_point": 5}
blk.add_mtext('\\A1;2.500', dxfattribs=at)
blk = doc.blocks.new('*D37')
at = {"layer": 'Defpoints', "color": 0}
for p in [(7.29, 10.766), (11.25, 8.75), (7.29, 8.372)]:
    blk.add_point(p, dxfattribs=at)
at = {"layer": 'dimensions', "color": 0, "lineweight": -2}
for p, q in [((7.29, 8.434), (7.29, 10.946)), ((11.25, 8.812), (11.25, 10.946)), ((7.47, 10.766), (8.988, 10.766)), ((11.07, 10.766), (9.552, 10.766))]:
    blk.add_line(p, q, dxfattribs=at)
at = {"layer": 'dimensions', "color": 0}
for points in [[(7.47, 10.796), (7.47, 10.736), (7.29, 10.766)], [(11.07, 10.796), (11.07, 10.736), (11.25, 10.766)]]:
    blk.add_solid(points, dxfattribs=at)
at = {"layer": 'dimensions', "color": 0, "insert": (9.27, 10.766), "char_height": 0.1, "attachment_point": 5}
blk.add_mtext('\\A1;3.960', dxfattribs=at)
blk = doc.blocks.new('*D38')
at = {"layer": 'Defpoints', "color": 0}
for p in [(7.46, 10.294), (11.25, 8.75), (7.46, 8.294)]:
    blk.add_point(p, dxfattribs=at)
at = {"layer": 'dimensions', "color": 0, "lineweight": -2}
for p, q in [((7.46, 8.356), (7.46, 10.474)), ((11.25, 8.812), (11.25, 10.474)), ((7.64, 10.294), (9.073, 10.294)), ((11.07, 10.294), (9.637, 10.294))]:
    blk.add_line(p, q, dxfattribs=at)
at = {"layer": 'dimensions', "color": 0}
for points in [[(7.64, 10.324), (7.64, 10.264), (7.46, 10.294)], [(11.07, 10.324), (11.07, 10.264), (11.25, 10.294)]]:
    blk.add_solid(points, dxfattribs=at)
at = {"layer": 'dimensions', "color": 0, "insert": (9.355, 10.294), "char_height": 0.1, "attachment_point": 5}
blk.add_mtext('\\A1;3.790', dxfattribs=at)
blk = doc.blocks.new('*D39')
at = {"layer": 'Defpoints', "color": 0}
for p in [(8.45, 10.026), (11.25, 8.75), (8.45, 8.45)]:
    blk.add_point(p, dxfattribs=at)
at = {"layer": 'dimensions', "color": 0, "lineweight": -2}
for p, q in [((8.45, 8.513), (8.45, 10.206)), ((11.25, 8.812), (11.25, 10.206)), ((8.63, 10.026), (9.577, 10.026)), ((11.07, 10.026), (10.123, 10.026))]:
    blk.add_line(p, q, dxfattribs=at)
at = {"layer": 'dimensions', "color": 0}
for points in [[(8.63, 10.056), (8.63, 9.996), (8.45, 10.026)], [(11.07, 10.056), (11.07, 9.996), (11.25, 10.026)]]:
    blk.add_solid(points, dxfattribs=at)
at = {"layer": 'dimensions', "color": 0, "insert": (9.85, 10.026), "char_height": 0.1, "attachment_point": 5}
blk.add_mtext('\\A1;2.800', dxfattribs=at)
blk = doc.blocks.new('*D40')
at = {"layer": 'Defpoints', "color": 0}
for p in [(9.15, 9.519), (11.25, 8.75), (9.15, 8.375)]:
    blk.add_point(p, dxfattribs=at)
at = {"layer": 'dimensions', "color": 0, "lineweight": -2}
for p, q in [((9.15, 8.438), (9.15, 9.699)), ((11.25, 8.812), (11.25, 9.699)), ((9.33, 9.519), (9.943, 9.519)), ((11.07, 9.519), (10.457, 9.519))]:
    blk.add_line(p, q, dxfattribs=at)
at = {"layer": 'dimensions', "color": 0}
for points in [[(9.33, 9.549), (9.33, 9.489), (9.15, 9.519)], [(11.07, 9.549), (11.07, 9.489), (11.25, 9.519)]]:
    blk.add_solid(points, dxfattribs=at)
at = {"layer": 'dimensions', "color": 0, "insert": (10.2, 9.519), "char_height": 0.1, "attachment_point": 5}
blk.add_mtext('\\A1;2.100', dxfattribs=at)
blk = doc.blocks.new('*D41')
at = {"layer": 'Defpoints', "color": 0}
for p in [(9.625, 9.196), (11.25, 8.75), (9.625, 8.375)]:
    blk.add_point(p, dxfattribs=at)
at = {"layer": 'dimensions', "color": 0, "lineweight": -2}
for p, q in [((9.625, 8.438), (9.625, 9.376)), ((11.25, 8.812), (11.25, 9.376)), ((9.805, 9.196), (10.164, 9.196)), ((11.07, 9.196), (10.711, 9.196))]:
    blk.add_line(p, q, dxfattribs=at)
at = {"layer": 'dimensions', "color": 0}
for points in [[(9.805, 9.226), (9.805, 9.166), (9.625, 9.196)], [(11.07, 9.226), (11.07, 9.166), (11.25, 9.196)]]:
    blk.add_solid(points, dxfattribs=at)
at = {"layer": 'dimensions', "color": 0, "insert": (10.438, 9.196), "char_height": 0.1, "attachment_point": 5}
blk.add_mtext('\\A1;1.625', dxfattribs=at)
blk = doc.blocks.new('*D42')
at = {"layer": 'Defpoints', "color": 0}
for p in [(6.08, 11.182), (6.08, 8.75), (11.25, 8.75)]:
    blk.add_point(p, dxfattribs=at)
at = {"layer": 'dimensions', "color": 0, "lineweight": -2}
for p, q in [((6.08, 8.812), (6.08, 11.362)), ((11.25, 8.812), (11.25, 11.362)), ((6.26, 11.182), (8.4, 11.182)), ((11.07, 11.182), (8.93, 11.182))]:
    blk.add_line(p, q, dxfattribs=at)
at = {"layer": 'dimensions', "color": 0}
for points in [[(6.26, 11.212), (6.26, 11.152), (6.08, 11.182)], [(11.07, 11.212), (11.07, 11.152), (11.25, 11.182)]]:
    blk.add_solid(points, dxfattribs=at)
at = {"layer": 'dimensions', "color": 0, "insert": (8.665, 11.182), "char_height": 0.1, "attachment_point": 5}
blk.add_mtext('\\A1;5.170', dxfattribs=at)
blk = doc.blocks.new('*D43')
at = {"layer": 'Defpoints', "color": 0}
for p in [(5.77, 8.67815), (5.77, 8.52185)]:
    blk.add_point(p, dxfattribs=at)
at = {"layer": 'dimensions', "color": 0, "lineweight": -2}
for p, q in [((5.95, 9.03815), (5.77, 9.03815)), ((5.77, 9.03815), (5.77, 8.85815)), ((5.77, 8.51), (5.77, 8.69)), ((5.68, 8.6), (5.86, 8.6))]:
    blk.add_line(p, q, dxfattribs=at)
at = {"layer": 'dimensions', "color": 0}
blk.add_solid([(5.74, 8.85815), (5.8, 8.85815), (5.77, 8.67815)], dxfattribs=at)
at = {"layer": 'dimensions', "color": 0, "insert": (6.265, 9.03815), "char_height": 0.1, "attachment_point": 5}
blk.add_mtext('\\A1;∅0.156', dxfattribs=at)
blk = doc.blocks.new('*D53')
at = {"layer": 'Defpoints', "color": 0}
for p in [(8.8, 14.863), (11.25, 14.5), (8.8, 13.938)]:
    blk.add_point(p, dxfattribs=at)
at = {"layer": 'dimensions', "color": 0, "lineweight": -2}
for p, q in [((8.8, 14.8), (8.8, 13.758)), ((11.25, 14.438), (11.25, 13.758)), ((8.98, 13.938), (9.743, 13.938)), ((11.07, 13.938), (10.307, 13.938))]:
    blk.add_line(p, q, dxfattribs=at)
at = {"layer": 'dimensions', "color": 0}
for points in [[(8.98, 13.968), (8.98, 13.908), (8.8, 13.938)], [(11.07, 13.968), (11.07, 13.908), (11.25, 13.938)]]:
    blk.add_solid(points, dxfattribs=at)
at = {"layer": 'dimensions', "color": 0, "insert": (10.025, 13.938), "char_height": 0.1, "attachment_point": 5}
blk.add_mtext('\\A1;2.450', dxfattribs=at)
blk = doc.blocks.new('*D54')
at = {"layer": 'Defpoints', "color": 0}
for p in [(8.861, 15.227), (8.739, 14.873)]:
    blk.add_point(p, dxfattribs=at)
at = {"layer": 'dimensions', "color": 0, "lineweight": -2}
for p, q in [((8.977, 15.568), (8.919, 15.398)), ((9.157, 15.568), (8.977, 15.568)), ((8.8, 14.96), (8.8, 15.14)), ((8.71, 15.05), (8.89, 15.05))]:
    blk.add_line(p, q, dxfattribs=at)
at = {"layer": 'dimensions', "color": 0}
blk.add_solid([(8.89, 15.407), (8.947, 15.388), (8.861, 15.227)], dxfattribs=at)
at = {"layer": 'dimensions', "color": 0, "insert": (9.489, 15.568), "char_height": 0.1, "attachment_point": 5}
blk.add_mtext('\\A1;∅0.375', dxfattribs=at)
blk = doc.blocks.new('*D55')
at = {"layer": 'Defpoints', "color": 0}
for p in [(8.35, 15.05), (11.25, 14.5), (8.35, 13.482)]:
    blk.add_point(p, dxfattribs=at)
at = {"layer": 'dimensions', "color": 0, "lineweight": -2}
for p, q in [((8.35, 14.988), (8.35, 13.302)), ((11.25, 14.438), (11.25, 13.302)), ((8.53, 13.482), (9.527, 13.482)), ((11.07, 13.482), (10.073, 13.482))]:
    blk.add_line(p, q, dxfattribs=at)
at = {"layer": 'dimensions', "color": 0}
for points in [[(8.53, 13.512), (8.53, 13.452), (8.35, 13.482)], [(11.07, 13.512), (11.07, 13.452), (11.25, 13.482)]]:
    blk.add_solid(points, dxfattribs=at)
at = {"layer": 'dimensions', "color": 0, "insert": (9.8, 13.482), "char_height": 0.1, "attachment_point": 5}
blk.add_mtext('\\A1;2.900', dxfattribs=at)
blk = doc.blocks.new('*D65')
at = {"layer": 'Defpoints', "color": 0}
for p in [(7.301, 7.918), (7.435, 7.838)]:
    blk.add_point(p, dxfattribs=at)
at = {"layer": 'dimensions', "color": 0, "lineweight": -2}
for p, q in [((6.614, 8.458), (6.384, 8.458)), ((6.384, 8.458), (7.146, 8.009)), ((7.368, 7.788), (7.368, 7.968)), ((7.278, 7.878), (7.458, 7.878))]:
    blk.add_line(p, q, dxfattribs=at)
at = {"layer": 'dimensions', "color": 0}
blk.add_solid([(7.161, 8.035), (7.13, 7.983), (7.301, 7.918)], dxfattribs=at)
at = {"layer": 'dimensions', "color": 0, "insert": (6.929, 8.458), "char_height": 0.1, "attachment_point": 5}
blk.add_mtext('\\A1;∅0.156', dxfattribs=at)
blk = doc.blocks.new('*D69')
at = {"layer": 'Defpoints', "color": 0, "linetype": 'ACAD_ISO03W100'}
for p in [(8.8, 15.05), (8.8, 14.5), (9.262, 14.5)]:
    blk.add_point(p, dxfattribs=at)
at = {"layer": 'dimensions', "color": 0, "linetype": 'ACAD_ISO03W100', "lineweight": -2}
for p, q in [((9.262, 15.23), (9.262, 15.41)), ((8.863, 15.05), (9.442, 15.05)), ((8.863, 14.5), (9.442, 14.5)), ((9.262, 14.32), (9.262, 14.14))]:
    blk.add_line(p, q, dxfattribs=at)
at = {"layer": 'dimensions', "color": 0, "linetype": 'ACAD_ISO03W100'}
for points in [[(9.232, 15.23), (9.292, 15.23), (9.262, 15.05)], [(9.232, 14.32), (9.292, 14.32), (9.262, 14.5)]]:
    blk.add_solid(points, dxfattribs=at)
at = {"layer": 'dimensions', "color": 0, "linetype": 'ACAD_ISO03W100', "insert": (9.262, 14.765), "char_height": 0.1, "attachment_point": 5}
blk.add_mtext('\\A1;0.550', dxfattribs=at)
blk = doc.blocks.new('*D71')
at = {"layer": 'Defpoints', "color": 0, "linetype": 'ByBlock'}
for p in [(7.36, 14.785), (7.36, 14.5), (7.515, 14.5)]:
    blk.add_point(p, dxfattribs=at)
at = {"layer": 'dimensions', "color": 0, "linetype": 'ByBlock', "lineweight": -2}
for p, q in [((7.515, 14.965), (7.515, 15.145)), ((7.423, 14.785), (7.695, 14.785)), ((7.423, 14.5), (7.695, 14.5)), ((7.515, 14.32), (7.515, 14.14))]:
    blk.add_line(p, q, dxfattribs=at)
at = {"layer": 'dimensions', "color": 0, "linetype": 'ByBlock'}
for points in [[(7.485, 14.965), (7.545, 14.965), (7.515, 14.785)], [(7.485, 14.32), (7.545, 14.32), (7.515, 14.5)]]:
    blk.add_solid(points, dxfattribs=at)
at = {"layer": 'dimensions', "color": 0, "linetype": 'ByBlock', "insert": (7.515, 14.643), "char_height": 0.1, "attachment_point": 5}
blk.add_mtext('\\A1;0.285', dxfattribs=at)
blk = doc.blocks.new('*D72')
at = {"layer": 'Defpoints', "color": 0, "linetype": 'ByBlock'}
for p in [(3.525, 14.785), (1, 14.5), (3.525, 13.782)]:
    blk.add_point(p, dxfattribs=at)
at = {"layer": 'dimensions', "color": 0, "linetype": 'ByBlock', "lineweight": -2}
for p, q in [((3.525, 14.723), (3.525, 13.602)), ((1, 14.438), (1, 13.602)), ((1.18, 13.782), (1.973, 13.782)), ((3.345, 13.782), (2.553, 13.782))]:
    blk.add_line(p, q, dxfattribs=at)
at = {"layer": 'dimensions', "color": 0, "linetype": 'ByBlock'}
for points in [[(1.18, 13.812), (1.18, 13.752), (1, 13.782)], [(3.345, 13.812), (3.345, 13.752), (3.525, 13.782)]]:
    blk.add_solid(points, dxfattribs=at)
at = {"layer": 'dimensions', "color": 0, "linetype": 'ByBlock', "insert": (2.263, 13.782), "char_height": 0.1, "attachment_point": 5}
blk.add_mtext('\\A1;2.525', dxfattribs=at)
blk = doc.blocks.new('*D73')
at = {"layer": 'Defpoints', "color": 0, "linetype": 'ByBlock'}
for p in [(8.331, 15.158), (8.369, 14.942)]:
    blk.add_point(p, dxfattribs=at)
at = {"layer": 'dimensions', "color": 0, "linetype": 'ByBlock', "lineweight": -2}
for p, q in [((8.09, 15.512), (8.27, 15.512)), ((8.27, 15.512), (8.301, 15.335)), ((8.35, 14.96), (8.35, 15.14)), ((8.26, 15.05), (8.44, 15.05))]:
    blk.add_line(p, q, dxfattribs=at)
at = {"layer": 'dimensions', "color": 0, "linetype": 'ByBlock'}
blk.add_solid([(8.33, 15.34), (8.271, 15.33), (8.331, 15.158)], dxfattribs=at)
at = {"layer": 'dimensions', "color": 0, "linetype": 'ByBlock', "insert": (7.775, 15.512), "char_height": 0.1, "attachment_point": 5}
blk.add_mtext('\\A1;∅0.219', dxfattribs=at)
blk = doc.blocks.new('*D74')
at = {"color": 0, "linetype": 'ByBlock', "lineweight": -2}
for p, q in [((6.643, 17.089), (6.404, 15.873)), ((7.003, 17.089), (6.643, 17.089)), ((6.35, 15.51), (6.35, 15.69)), ((6.26, 15.6), (6.44, 15.6))]:
    blk.add_line(p, q, dxfattribs=at)
at = {"color": 0, "linetype": 'ByBlock'}
blk.add_solid([(6.374, 15.879), (6.433, 15.867), (6.369, 15.697)], dxfattribs=at)
at = {"layer": 'Defpoints', "color": 0, "linetype": 'ByBlock'}
for p in [(6.369, 15.697), (6.331, 15.503)]:
    blk.add_point(p, dxfattribs=at)
at = {"color": 0, "linetype": 'ByBlock', "insert": (7.318, 17.089), "char_height": 0.1, "attachment_point": 5}
blk.add_mtext('\\A1;∅0.197', dxfattribs=at)

msp = doc.modelspace()

# ---------------------------------------------------------------- hatches: boundary and pattern name
at = {"layer": 'dimensions'}
h = msp.add_hatch(dxfattribs=at)
h.set_pattern_fill('ANSI31', color=256, scale=0.25, style=0)
h.set_pattern_definition(pattern_1)
h.paths.add_polyline_path([(8.038, 8.75), (7.762, 8.75), (7.762, 8.45), (8.038, 8.45)])
h = msp.add_hatch(dxfattribs=at)
h.set_pattern_fill('ANSI31', color=256, scale=0.25, style=0)
h.set_pattern_definition(pattern_1)
h.paths.add_polyline_path([(7.762, 7.5), (8.038, 7.5), (8.038, 7.8), (7.762, 7.8)])
at = {"layer": 'lines', "linetype": 'ByBlock'}
h = msp.add_hatch(dxfattribs=at)
h.set_pattern_fill('ANSI31', color=256, scale=0.5, style=0)
h.paths.add_polyline_path([(7.375, 15.25), (3.525, 15.25), (3.525, 14.835), (7.375, 14.835)])
h = msp.add_hatch(dxfattribs=at)
h.set_pattern_fill('ANSI31', color=256, scale=0.5, angle=45, style=0)
h.paths.add_polyline_path([(7.375, 14.835), (3.525, 14.835), (3.525, 14.785), (7.375, 14.785)])
at = {"layer": 'lines'}
h = msp.add_hatch(dxfattribs=at)
h.set_pattern_fill('STEEL', color=256, angle=45, style=0)
h.set_pattern_definition([(90, (0, 0), (-0.125, 3e-17), []), (90, (-0.0442, 0.0442), (-0.125, 3e-17), [])])
edge = h.paths.add_edge_path()
edge.add_line((3.5, 14.55), (9.5, 14.55))
edge.add_line((10.95, 14.5), (1, 14.5))

# ---------------------------------------------------------------- linework, layer by layer
at = {"layer": 'dimensions'}
for p, q in [((7.9, 15.79), (7.9, 15.97)), ((7.81, 15.88), (7.99, 15.88)), ((6.35, 15.51), (6.35, 15.69)), ((6.26, 15.6), (6.44, 15.6)), ((5.62, 15.16), (5.62, 15.34)), ((9.63, 15.21), (9.63, 15.39)), ((5.53, 15.25), (5.71, 15.25)), ((9.54, 15.3), (9.72, 15.3)), ((8.35, 14.96), (8.35, 15.14)), ((8.8, 14.96), (8.8, 15.14)), ((8.26, 15.05), (8.44, 15.05)), ((8.8, 15.05), (8.35, 15.05)), ((8.71, 15.05), (8.89, 15.05)), ((10.65, 14.71), (10.65, 14.89)), ((10.56, 14.8), (10.74, 14.8)), ((5.77, 8.51), (5.77, 8.69)), ((6.08, 8.51), (6.08, 8.69)), ((7.762, 8.45), (7.762, 8.75)), ((8.038, 8.45), (8.038, 8.75)), ((5.68, 8.6), (5.86, 8.6)), ((5.99, 8.6), (6.17, 8.6)), ((7.3681, 8.2819), (7.3681, 8.4619)), ((7.2781, 8.3719), (7.4581, 8.3719)), ((7.29, 8.3719), (7.29, 8.3719)), ((8.45, 8.125), (8.45, 8.45)), ((8.75, 8.035), (8.75, 8.215)), ((8.66, 8.125), (8.84, 8.125)), ((7.3681, 7.7881), (7.3681, 7.9681)), ((7.2781, 7.8781), (7.4581, 7.8781)), ((7.29, 7.8781), (7.29, 7.8781)), ((7.762, 7.8), (7.762, 7.5)), ((8.038, 7.7956), (8.038, 7.5)), ((5.77, 7.56), (5.77, 7.74)), ((6.08, 7.56), (6.08, 7.74)), ((5.68, 7.65), (5.86, 7.65)), ((5.99, 7.65), (6.17, 7.65))]:
    msp.add_line(p, q, dxfattribs=at)
at = {"layer": 'dimensions', "linetype": 'ByBlock'}
msp.add_line((3.525, 14.785), (3.525, 14.835), dxfattribs=at)
at = {"layer": 'lines', "color": 1}
for p, q in [((11.25, 16.25), (1, 15.8)), ((11.25, 16.25), (11.25, 14.7)), ((8.35, 15.1594), (8.6477, 15.1594)), ((8.35, 14.9406), (8.6477, 14.9406)), ((10.95, 14.5), (10.95, 14.7)), ((10.95, 14.7), (11.25, 14.7)), ((3.5, 14.55), (9.5, 14.55)), ((3.5, 14.5), (3.5, 14.55)), ((9.5, 14.5), (9.5, 14.55)), ((1, 8.75), (11.25, 8.75)), ((11.25, 7.5), (11.25, 8.75)), ((5.445, 8.625), (3.5095, 8.625)), ((5.57, 7.75), (5.57, 8.5)), ((8.45, 8.45), (7.3681, 8.45)), ((8.45, 8.125), (8.45, 8.45)), ((9.15, 7.875), (9.15, 8.375)), ((9.15, 8.375), (9.625, 8.375)), ((9.625, 7.875), (9.625, 8.375)), ((7.46, 8.2938), (7.3681, 8.2938)), ((7.46, 8.2938), (7.46, 7.9562)), ((8.45, 8.125), (8.45, 7.8)), ((7.46, 7.9562), (7.3681, 7.9562)), ((9.625, 7.875), (9.15, 7.875)), ((8.45, 7.8), (7.3681, 7.8)), ((5.445, 7.625), (3.5095, 7.625)), ((1, 7.5), (11.25, 7.5))]:
    msp.add_line(p, q, dxfattribs=at)
at = {"layer": 'lines', "linetype": 'ByBlock'}
for p, q in [((3.525, 14.785), (3.525, 15.25)), ((7.375, 15.25), (3.525, 15.25)), ((7.375, 14.785), (7.375, 15.25)), ((3.525, 14.835), (7.375, 14.835)), ((3.525, 14.785), (7.375, 14.785)), ((1, 14.5), (10.95, 14.5))]:
    msp.add_line(p, q, dxfattribs=at)
at = {"layer": 'lines', "color": 1}
for centre, radius in [((7.9, 15.88), 0.0985), ((6.35, 15.6), 0.0985), ((5.62, 15.25), 0.1), ((9.63, 15.3), 0.1094), ((10.65, 14.8), 0.1094), ((5.77, 8.6), 0.0781), ((6.08, 8.6), 0.0781), ((8.75, 8.125), 0.1094), ((5.77, 7.65), 0.0781), ((6.08, 7.65), 0.0781)]:
    msp.add_circle(centre, radius, dxfattribs=at)
for centre, radius, start, end in [((8.8, 15.05), 0.1875, 215.68533, 144.31467), ((8.35, 15.05), 0.1094, 90, 270), ((3.5095, 8.5469), 0.0781, 90, 111.03751), ((5.445, 8.5), 0.125, 0, 90), ((7.3681, 8.3719), 0.0781, 90, 180), ((7.3681, 8.3719), 0.0781, 180, 270), ((7.3681, 7.8781), 0.0781, 90, 180), ((7.3681, 7.8781), 0.0781, 180, 270), ((5.445, 7.75), 0.125, 270, 0), ((3.5095, 7.7031), 0.0781, 248.96249, 270)]:
    msp.add_arc(centre, radius, start, end, dxfattribs=at)

# ---------------------------------------------------------------- texts
at = {"layer": 'dimensions', "linetype": 'ByBlock', "char_height": 0.1, "attachment_point": 1}
for s, insert, width in [('Shape of lower rail is not accurate. Use dimensions for location only.', (2.9004, 17.1677), 2.3136), ('Lower rail location on inside of both sides. Ensure rail is parallel to upper rail. ', (4.2923, 14.011), 1.9272)]:
    msp.add_mtext(s, dxfattribs=dict(at, insert=insert, width=width))
at = {"layer": 'dimensions', "char_height": 0.1, "attachment_point": 1}
for s, insert, width in [('(5mm)', (7.2765, 16.9165), 0.8201), ('OMIT CUT-OUT FOR SINGLE ARM TRIGGER', (3.8768, 7.4186), 2.78242), ('File clearance for trigger pin with half round file before assembling receiver.', (7.9344, 7.4065), 3.3458)]:
    msp.add_mtext(s, dxfattribs=dict(at, insert=insert, width=width))

# ---------------------------------------------------------------- dimensions: what is measured, and where the dimension line sits
at = {"linetype": 'ByBlock'}
dim = msp.add_diameter_dim_2p(p1=(6.331, 15.5034), p2=(6.369, 15.6966), dimstyle='Standard', override={"dimtxt": 0.1}, dxfattribs=at)
dim.commit()
dim.dimension.update_dxf_attribs({"geometry": '*D74', "text_midpoint": (7.3184, 17.0891), "dimtype": 163})
at = {"layer": 'dimensions'}
for p1, p2, picture, middle in [((8.7394, 14.8726), (8.8606, 15.2274), '*D54', (9.4886, 15.5681)), ((5.77, 8.5219), (5.77, 8.6782), '*D43', (6.265, 9.0382))]:
    dim = msp.add_diameter_dim_2p(p1=p1, p2=p2, dimstyle='Standard', override={"dimtxt": 0.1}, dxfattribs=at)
    dim.commit()
    dim.dimension.update_dxf_attribs({"geometry": picture, "text_midpoint": middle})
at = {"layer": 'dimensions', "linetype": 'ByBlock'}
dim = msp.add_diameter_dim_2p(p1=(8.3687, 14.9422), p2=(8.3313, 15.1578), dimstyle='Standard', override={"dimtxt": 0.1}, dxfattribs=at)
dim.commit()
dim.dimension.update_dxf_attribs({"geometry": '*D73', "text_midpoint": (7.7749, 15.5125)})
at = {"layer": 'dimensions', "linetype": 'ACAD_ISO03W100'}
dim = msp.add_linear_dim(base=(9.2616, 14.5), p1=(8.8, 15.05), p2=(8.8, 14.5), angle=90, dimstyle='Standard', override={"dimtxt": 0.1}, dxfattribs=at)
dim.commit()
dim.dimension.update_dxf_attribs({"geometry": '*D69', "text_midpoint": (9.2616, 14.765), "dimtype": 160})
at = {"layer": 'dimensions', "linetype": 'ByBlock'}
dim = msp.add_linear_dim(base=(7.515, 14.5), p1=(7.3604, 14.785), p2=(7.3604, 14.5), angle=90, dimstyle='Standard', override={"dimtxt": 0.1}, dxfattribs=at)
dim.commit()
dim.dimension.update_dxf_attribs({"geometry": '*D71', "text_midpoint": (7.515, 14.6425)})
at = {"layer": 'dimensions'}
for base, p1, p2, picture, middle in [((8.35, 13.482), (11.25, 14.5), (8.35, 15.05), '*D55', (9.8, 13.482)), ((8.8, 13.9384), (11.25, 14.5), (8.8, 14.8625), '*D53', (10.025, 13.9384)), ((7.29, 10.7665), (11.25, 8.75), (7.29, 8.3719), '*D37', (9.27, 10.7665)), ((7.46, 10.2939), (11.25, 8.75), (7.46, 8.2938), '*D38', (9.355, 10.2939)), ((8.75, 9.7896), (11.25, 8.75), (8.75, 8.2344), '*D36', (10, 9.7896)), ((9.15, 9.5195), (11.25, 8.75), (9.15, 8.375), '*D40', (10.2, 9.5195))]:
    dim = msp.add_linear_dim(base=base, p1=p1, p2=p2, dimstyle='Standard', override={"dimtxt": 0.1}, dxfattribs=at)
    dim.commit()
    dim.dimension.update_dxf_attribs({"geometry": picture, "text_midpoint": middle})
at = {"layer": 'dimensions', "linetype": 'ByBlock'}
dim = msp.add_linear_dim(base=(3.525, 13.7824), p1=(1, 14.5), p2=(3.525, 14.785), dimstyle='Standard', override={"dimtxt": 0.1}, dxfattribs=at)
dim.commit()
dim.dimension.update_dxf_attribs({"geometry": '*D72', "text_midpoint": (2.2625, 13.7824)})
at = {"layer": 'dimensions'}
for base, p1, p2, picture, middle in [((2.77, 12.5543), (11.25, 8.75), (2.77, 8.75), '*D7', (7.01, 12.5543)), ((11.25, 12.1201), (3.495, 8.75), (11.25, 8.75), '*D8', (7.0408, 12.1201)), ((11.25, 11.5492), (5.57, 8.5), (11.25, 8.75), '*D35', (8.41, 11.5492)), ((6.08, 11.1821), (11.25, 8.75), (6.08, 8.75), '*D42', (8.665, 11.1821)), ((8.45, 10.0265), (11.25, 8.75), (8.45, 8.45), '*D39', (9.85, 10.0265)), ((9.625, 9.1957), (11.25, 8.75), (9.625, 8.375), '*D41', (10.4375, 9.1957)), ((3.3, 9.0399), (2.77, 8.575), (3.3, 8.575), '*D17', (3.035, 9.0399))]:
    dim = msp.add_linear_dim(base=base, p1=p1, p2=p2, dimstyle='Standard', override={"dimtxt": 0.1}, dxfattribs=at)
    dim.commit()
    dim.dimension.update_dxf_attribs({"geometry": picture, "text_midpoint": middle, "dimtype": 160})
for base, p1, p2, angle, override, picture, middle, dimtype in [((9.965, 7.875), (9.625, 8.375), (9.625, 7.875), 270, {"dimtxt": 0.1, "dimtofl": 1}, '*D20', (10.41, 8.9021), 161), ((8.2569, 7.8), (8.45, 8.45), (8.45, 7.8), 90, {"dimtxt": 0.1}, '*D19', (8.2569, 8.1129), 160), ((5.9344, 7.65), (6.08, 8.6), (6.08, 7.65), 90, {"dimtxt": 0.1}, '*D18', (5.9344, 8.125), 160)]:
    dim = msp.add_linear_dim(base=base, p1=p1, p2=p2, angle=angle, dimstyle='Standard', override=override, dxfattribs=at)
    dim.commit()
    dim.dimension.update_dxf_attribs({"geometry": picture, "text_midpoint": middle, "dimtype": dimtype})
for base, p1, p2, picture, middle in [((11.8862, 7.5), (11.25, 8.75), (11.25, 7.5), '*D21', (11.8862, 8.125)), ((3.8063, 7.625), (3.5095, 8.625), (3.5095, 7.625), '*D9', (3.8063, 8.125))]:
    dim = msp.add_linear_dim(base=base, p1=p1, p2=p2, angle=90, dimstyle='Standard', override={"dimtxt": 0.1}, dxfattribs=at)
    dim.commit()
    dim.dimension.update_dxf_attribs({"geometry": picture, "text_midpoint": middle})
dim = msp.add_radius_dim(center=(5.445, 8.5), mpoint=(5.5696, 8.5097), dimstyle='Standard', override={"dimtxt": 0.1, "dimtmove": 1}, dxfattribs=at)
dim.commit()
dim.dimension.update_dxf_attribs({"geometry": '*D6', "text_midpoint": (4.7721, 8.4478), "dimtype": 164})
for p1, p2, picture, middle in [((7.4354, 7.8385), (7.3008, 7.9178), '*D65', (6.9291, 8.4578)), ((8.75, 8.2344), (8.75, 8.0156), '*D22', (9.295, 7.62))]:
    dim = msp.add_diameter_dim_2p(p1=p1, p2=p2, dimstyle='Standard', override={"dimtxt": 0.1}, dxfattribs=at)
    dim.commit()
    dim.dimension.update_dxf_attribs({"geometry": picture, "text_midpoint": middle, "dimtype": 163})

# ---------------------------------------------------------------- leaders
at = {"layer": 'dimensions', "linetype": 'ByBlock'}
for points in [[(4.0247, 15.25), (2.3772, 17.0863), (2.6562, 17.0863)], [(4.3552, 14.785), (3.8994, 14.0073), (4.0477, 14.0087)]]:
    msp.add_leader(points, dimstyle='Standard', override={"dimgap": 0.09, "dimtad": 0}, dxfattribs=at)
at = {"layer": 'dimensions'}
for points in [[(7.9, 15.97), (6.6434, 17.0891)], [(7.2781, 8.3719), (6.7335, 7.3525), (6.5585, 7.3559)], [(7.8749, 7.5), (7.5833, 7.1975), (7.71, 7.1975)]]:
    msp.add_leader(points, dimstyle='Standard', override={"dimgap": 0.09, "dimtad": 0}, dxfattribs=at)

doc.saveas('drawing.dxf')
